# 
#              Synchronous High Speed Single Port SRAM Compiler 
# 
#                    UMC 0.18um GenericII Logic Process
#    __________________________________________________________________________
# 
# 
#      (C) Copyright 2002-2009 Faraday Technology Corp. All Rights Reserved.
#    
#    This source code is an unpublished work belongs to Faraday Technology
#    Corp.  It is considered a trade secret and is not to be divulged or
#    used by parties who have not received written authorization from
#    Faraday Technology Corp.
#    
#    Faraday's home page can be found at:
#    http://www.faraday-tech.com/
#   
#       Module Name      : SUMA180_4096X12
#       Words            : 4096
#       Bits             : 12
#       Byte-Write       : 1
#       Aspect Ratio     : 4
#       Output Loading   : 0.05  (pf)
#       Data Slew        : 0.02  (ns)
#       CK Slew          : 0.02  (ns)
#       Power Ring Width : 2  (um)
# 
# -----------------------------------------------------------------------------
# 
#       Library          : FSA0M_A
#       Memaker          : 200901.2.1
#       Date             : 2026/05/01 20:58:27
# 
# -----------------------------------------------------------------------------


NAMESCASESENSITIVE ON ;
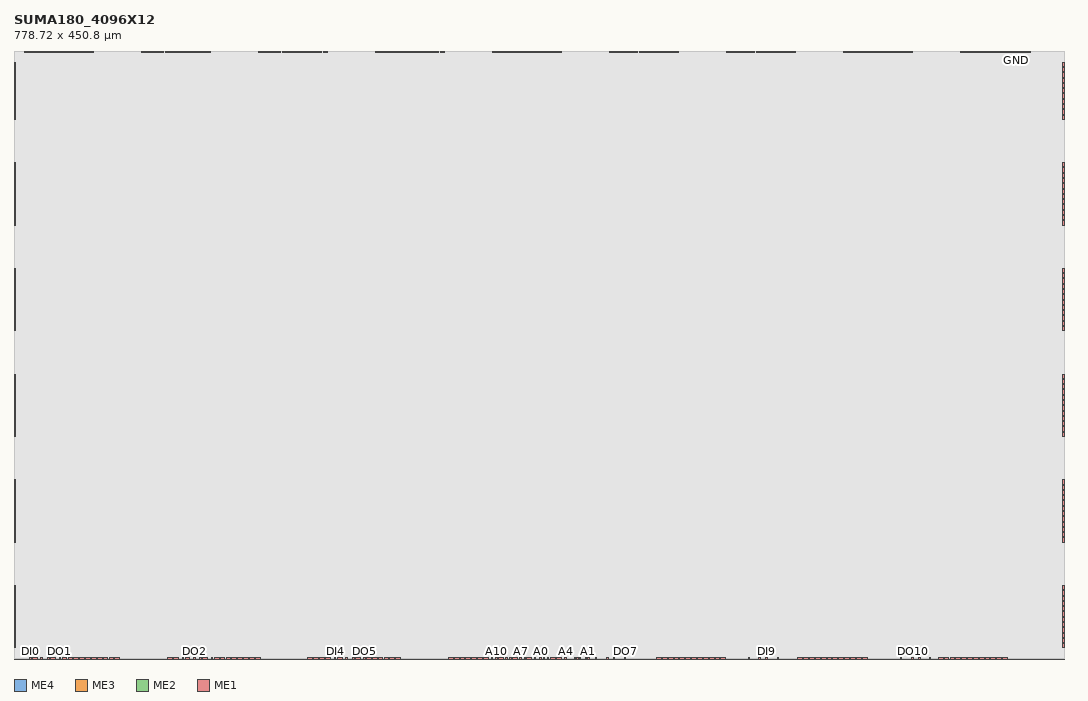
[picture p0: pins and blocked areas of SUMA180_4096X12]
MACRO SUMA180_4096X12
CLASS BLOCK ;
FOREIGN SUMA180_4096X12 0.000 0.000 ;
ORIGIN 0.000 0.000 ;
SIZE 778.720 BY 450.800 ;
SYMMETRY x y r90 ;
SITE core ;
PIN VCC
  DIRECTION INOUT ;
  USE POWER ;
  SHAPE ABUTMENT ;
 PORT
  LAYER ME4 ;
  RECT 777.600 439.380 778.720 442.620 ;
  LAYER ME3 ;
  RECT 777.600 439.380 778.720 442.620 ;
  LAYER ME2 ;
  RECT 777.600 439.380 778.720 442.620 ;
  LAYER ME1 ;
  RECT 777.600 439.380 778.720 442.620 ;
 END
 PORT
  LAYER ME4 ;
  RECT 777.600 431.540 778.720 434.780 ;
  LAYER ME3 ;
  RECT 777.600 431.540 778.720 434.780 ;
  LAYER ME2 ;
  RECT 777.600 431.540 778.720 434.780 ;
  LAYER ME1 ;
  RECT 777.600 431.540 778.720 434.780 ;
 END
 PORT
  LAYER ME4 ;
  RECT 777.600 423.700 778.720 426.940 ;
  LAYER ME3 ;
  RECT 777.600 423.700 778.720 426.940 ;
  LAYER ME2 ;
  RECT 777.600 423.700 778.720 426.940 ;
  LAYER ME1 ;
  RECT 777.600 423.700 778.720 426.940 ;
 END
 PORT
  LAYER ME4 ;
  RECT 777.600 415.860 778.720 419.100 ;
  LAYER ME3 ;
  RECT 777.600 415.860 778.720 419.100 ;
  LAYER ME2 ;
  RECT 777.600 415.860 778.720 419.100 ;
  LAYER ME1 ;
  RECT 777.600 415.860 778.720 419.100 ;
 END
 PORT
  LAYER ME4 ;
  RECT 777.600 408.020 778.720 411.260 ;
  LAYER ME3 ;
  RECT 777.600 408.020 778.720 411.260 ;
  LAYER ME2 ;
  RECT 777.600 408.020 778.720 411.260 ;
  LAYER ME1 ;
  RECT 777.600 408.020 778.720 411.260 ;
 END
 PORT
  LAYER ME4 ;
  RECT 777.600 400.180 778.720 403.420 ;
  LAYER ME3 ;
  RECT 777.600 400.180 778.720 403.420 ;
  LAYER ME2 ;
  RECT 777.600 400.180 778.720 403.420 ;
  LAYER ME1 ;
  RECT 777.600 400.180 778.720 403.420 ;
 END
 PORT
  LAYER ME4 ;
  RECT 777.600 360.980 778.720 364.220 ;
  LAYER ME3 ;
  RECT 777.600 360.980 778.720 364.220 ;
  LAYER ME2 ;
  RECT 777.600 360.980 778.720 364.220 ;
  LAYER ME1 ;
  RECT 777.600 360.980 778.720 364.220 ;
 END
 PORT
  LAYER ME4 ;
  RECT 777.600 353.140 778.720 356.380 ;
  LAYER ME3 ;
  RECT 777.600 353.140 778.720 356.380 ;
  LAYER ME2 ;
  RECT 777.600 353.140 778.720 356.380 ;
  LAYER ME1 ;
  RECT 777.600 353.140 778.720 356.380 ;
 END
 PORT
  LAYER ME4 ;
  RECT 777.600 345.300 778.720 348.540 ;
  LAYER ME3 ;
  RECT 777.600 345.300 778.720 348.540 ;
  LAYER ME2 ;
  RECT 777.600 345.300 778.720 348.540 ;
  LAYER ME1 ;
  RECT 777.600 345.300 778.720 348.540 ;
 END
 PORT
  LAYER ME4 ;
  RECT 777.600 337.460 778.720 340.700 ;
  LAYER ME3 ;
  RECT 777.600 337.460 778.720 340.700 ;
  LAYER ME2 ;
  RECT 777.600 337.460 778.720 340.700 ;
  LAYER ME1 ;
  RECT 777.600 337.460 778.720 340.700 ;
 END
 PORT
  LAYER ME4 ;
  RECT 777.600 329.620 778.720 332.860 ;
  LAYER ME3 ;
  RECT 777.600 329.620 778.720 332.860 ;
  LAYER ME2 ;
  RECT 777.600 329.620 778.720 332.860 ;
  LAYER ME1 ;
  RECT 777.600 329.620 778.720 332.860 ;
 END
 PORT
  LAYER ME4 ;
  RECT 777.600 321.780 778.720 325.020 ;
  LAYER ME3 ;
  RECT 777.600 321.780 778.720 325.020 ;
  LAYER ME2 ;
  RECT 777.600 321.780 778.720 325.020 ;
  LAYER ME1 ;
  RECT 777.600 321.780 778.720 325.020 ;
 END
 PORT
  LAYER ME4 ;
  RECT 777.600 282.580 778.720 285.820 ;
  LAYER ME3 ;
  RECT 777.600 282.580 778.720 285.820 ;
  LAYER ME2 ;
  RECT 777.600 282.580 778.720 285.820 ;
  LAYER ME1 ;
  RECT 777.600 282.580 778.720 285.820 ;
 END
 PORT
  LAYER ME4 ;
  RECT 777.600 274.740 778.720 277.980 ;
  LAYER ME3 ;
  RECT 777.600 274.740 778.720 277.980 ;
  LAYER ME2 ;
  RECT 777.600 274.740 778.720 277.980 ;
  LAYER ME1 ;
  RECT 777.600 274.740 778.720 277.980 ;
 END
 PORT
  LAYER ME4 ;
  RECT 777.600 266.900 778.720 270.140 ;
  LAYER ME3 ;
  RECT 777.600 266.900 778.720 270.140 ;
  LAYER ME2 ;
  RECT 777.600 266.900 778.720 270.140 ;
  LAYER ME1 ;
  RECT 777.600 266.900 778.720 270.140 ;
 END
 PORT
  LAYER ME4 ;
  RECT 777.600 259.060 778.720 262.300 ;
  LAYER ME3 ;
  RECT 777.600 259.060 778.720 262.300 ;
  LAYER ME2 ;
  RECT 777.600 259.060 778.720 262.300 ;
  LAYER ME1 ;
  RECT 777.600 259.060 778.720 262.300 ;
 END
 PORT
  LAYER ME4 ;
  RECT 777.600 251.220 778.720 254.460 ;
  LAYER ME3 ;
  RECT 777.600 251.220 778.720 254.460 ;
  LAYER ME2 ;
  RECT 777.600 251.220 778.720 254.460 ;
  LAYER ME1 ;
  RECT 777.600 251.220 778.720 254.460 ;
 END
 PORT
  LAYER ME4 ;
  RECT 777.600 243.380 778.720 246.620 ;
  LAYER ME3 ;
  RECT 777.600 243.380 778.720 246.620 ;
  LAYER ME2 ;
  RECT 777.600 243.380 778.720 246.620 ;
  LAYER ME1 ;
  RECT 777.600 243.380 778.720 246.620 ;
 END
 PORT
  LAYER ME4 ;
  RECT 777.600 204.180 778.720 207.420 ;
  LAYER ME3 ;
  RECT 777.600 204.180 778.720 207.420 ;
  LAYER ME2 ;
  RECT 777.600 204.180 778.720 207.420 ;
  LAYER ME1 ;
  RECT 777.600 204.180 778.720 207.420 ;
 END
 PORT
  LAYER ME4 ;
  RECT 777.600 196.340 778.720 199.580 ;
  LAYER ME3 ;
  RECT 777.600 196.340 778.720 199.580 ;
  LAYER ME2 ;
  RECT 777.600 196.340 778.720 199.580 ;
  LAYER ME1 ;
  RECT 777.600 196.340 778.720 199.580 ;
 END
 PORT
  LAYER ME4 ;
  RECT 777.600 188.500 778.720 191.740 ;
  LAYER ME3 ;
  RECT 777.600 188.500 778.720 191.740 ;
  LAYER ME2 ;
  RECT 777.600 188.500 778.720 191.740 ;
  LAYER ME1 ;
  RECT 777.600 188.500 778.720 191.740 ;
 END
 PORT
  LAYER ME4 ;
  RECT 777.600 180.660 778.720 183.900 ;
  LAYER ME3 ;
  RECT 777.600 180.660 778.720 183.900 ;
  LAYER ME2 ;
  RECT 777.600 180.660 778.720 183.900 ;
  LAYER ME1 ;
  RECT 777.600 180.660 778.720 183.900 ;
 END
 PORT
  LAYER ME4 ;
  RECT 777.600 172.820 778.720 176.060 ;
  LAYER ME3 ;
  RECT 777.600 172.820 778.720 176.060 ;
  LAYER ME2 ;
  RECT 777.600 172.820 778.720 176.060 ;
  LAYER ME1 ;
  RECT 777.600 172.820 778.720 176.060 ;
 END
 PORT
  LAYER ME4 ;
  RECT 777.600 164.980 778.720 168.220 ;
  LAYER ME3 ;
  RECT 777.600 164.980 778.720 168.220 ;
  LAYER ME2 ;
  RECT 777.600 164.980 778.720 168.220 ;
  LAYER ME1 ;
  RECT 777.600 164.980 778.720 168.220 ;
 END
 PORT
  LAYER ME4 ;
  RECT 777.600 125.780 778.720 129.020 ;
  LAYER ME3 ;
  RECT 777.600 125.780 778.720 129.020 ;
  LAYER ME2 ;
  RECT 777.600 125.780 778.720 129.020 ;
  LAYER ME1 ;
  RECT 777.600 125.780 778.720 129.020 ;
 END
 PORT
  LAYER ME4 ;
  RECT 777.600 117.940 778.720 121.180 ;
  LAYER ME3 ;
  RECT 777.600 117.940 778.720 121.180 ;
  LAYER ME2 ;
  RECT 777.600 117.940 778.720 121.180 ;
  LAYER ME1 ;
  RECT 777.600 117.940 778.720 121.180 ;
 END
 PORT
  LAYER ME4 ;
  RECT 777.600 110.100 778.720 113.340 ;
  LAYER ME3 ;
  RECT 777.600 110.100 778.720 113.340 ;
  LAYER ME2 ;
  RECT 777.600 110.100 778.720 113.340 ;
  LAYER ME1 ;
  RECT 777.600 110.100 778.720 113.340 ;
 END
 PORT
  LAYER ME4 ;
  RECT 777.600 102.260 778.720 105.500 ;
  LAYER ME3 ;
  RECT 777.600 102.260 778.720 105.500 ;
  LAYER ME2 ;
  RECT 777.600 102.260 778.720 105.500 ;
  LAYER ME1 ;
  RECT 777.600 102.260 778.720 105.500 ;
 END
 PORT
  LAYER ME4 ;
  RECT 777.600 94.420 778.720 97.660 ;
  LAYER ME3 ;
  RECT 777.600 94.420 778.720 97.660 ;
  LAYER ME2 ;
  RECT 777.600 94.420 778.720 97.660 ;
  LAYER ME1 ;
  RECT 777.600 94.420 778.720 97.660 ;
 END
 PORT
  LAYER ME4 ;
  RECT 777.600 86.580 778.720 89.820 ;
  LAYER ME3 ;
  RECT 777.600 86.580 778.720 89.820 ;
  LAYER ME2 ;
  RECT 777.600 86.580 778.720 89.820 ;
  LAYER ME1 ;
  RECT 777.600 86.580 778.720 89.820 ;
 END
 PORT
  LAYER ME4 ;
  RECT 777.600 47.380 778.720 50.620 ;
  LAYER ME3 ;
  RECT 777.600 47.380 778.720 50.620 ;
  LAYER ME2 ;
  RECT 777.600 47.380 778.720 50.620 ;
  LAYER ME1 ;
  RECT 777.600 47.380 778.720 50.620 ;
 END
 PORT
  LAYER ME4 ;
  RECT 777.600 39.540 778.720 42.780 ;
  LAYER ME3 ;
  RECT 777.600 39.540 778.720 42.780 ;
  LAYER ME2 ;
  RECT 777.600 39.540 778.720 42.780 ;
  LAYER ME1 ;
  RECT 777.600 39.540 778.720 42.780 ;
 END
 PORT
  LAYER ME4 ;
  RECT 777.600 31.700 778.720 34.940 ;
  LAYER ME3 ;
  RECT 777.600 31.700 778.720 34.940 ;
  LAYER ME2 ;
  RECT 777.600 31.700 778.720 34.940 ;
  LAYER ME1 ;
  RECT 777.600 31.700 778.720 34.940 ;
 END
 PORT
  LAYER ME4 ;
  RECT 777.600 23.860 778.720 27.100 ;
  LAYER ME3 ;
  RECT 777.600 23.860 778.720 27.100 ;
  LAYER ME2 ;
  RECT 777.600 23.860 778.720 27.100 ;
  LAYER ME1 ;
  RECT 777.600 23.860 778.720 27.100 ;
 END
 PORT
  LAYER ME4 ;
  RECT 777.600 16.020 778.720 19.260 ;
  LAYER ME3 ;
  RECT 777.600 16.020 778.720 19.260 ;
  LAYER ME2 ;
  RECT 777.600 16.020 778.720 19.260 ;
  LAYER ME1 ;
  RECT 777.600 16.020 778.720 19.260 ;
 END
 PORT
  LAYER ME4 ;
  RECT 777.600 8.180 778.720 11.420 ;
  LAYER ME3 ;
  RECT 777.600 8.180 778.720 11.420 ;
  LAYER ME2 ;
  RECT 777.600 8.180 778.720 11.420 ;
  LAYER ME1 ;
  RECT 777.600 8.180 778.720 11.420 ;
 END
 PORT
  LAYER ME4 ;
  RECT 0.000 439.380 1.120 442.620 ;
  LAYER ME3 ;
  RECT 0.000 439.380 1.120 442.620 ;
  LAYER ME2 ;
  RECT 0.000 439.380 1.120 442.620 ;
  LAYER ME1 ;
  RECT 0.000 439.380 1.120 442.620 ;
 END
 PORT
  LAYER ME4 ;
  RECT 0.000 431.540 1.120 434.780 ;
  LAYER ME3 ;
  RECT 0.000 431.540 1.120 434.780 ;
  LAYER ME2 ;
  RECT 0.000 431.540 1.120 434.780 ;
  LAYER ME1 ;
  RECT 0.000 431.540 1.120 434.780 ;
 END
 PORT
  LAYER ME4 ;
  RECT 0.000 423.700 1.120 426.940 ;
  LAYER ME3 ;
  RECT 0.000 423.700 1.120 426.940 ;
  LAYER ME2 ;
  RECT 0.000 423.700 1.120 426.940 ;
  LAYER ME1 ;
  RECT 0.000 423.700 1.120 426.940 ;
 END
 PORT
  LAYER ME4 ;
  RECT 0.000 415.860 1.120 419.100 ;
  LAYER ME3 ;
  RECT 0.000 415.860 1.120 419.100 ;
  LAYER ME2 ;
  RECT 0.000 415.860 1.120 419.100 ;
  LAYER ME1 ;
  RECT 0.000 415.860 1.120 419.100 ;
 END
 PORT
  LAYER ME4 ;
  RECT 0.000 408.020 1.120 411.260 ;
  LAYER ME3 ;
  RECT 0.000 408.020 1.120 411.260 ;
  LAYER ME2 ;
  RECT 0.000 408.020 1.120 411.260 ;
  LAYER ME1 ;
  RECT 0.000 408.020 1.120 411.260 ;
 END
 PORT
  LAYER ME4 ;
  RECT 0.000 400.180 1.120 403.420 ;
  LAYER ME3 ;
  RECT 0.000 400.180 1.120 403.420 ;
  LAYER ME2 ;
  RECT 0.000 400.180 1.120 403.420 ;
  LAYER ME1 ;
  RECT 0.000 400.180 1.120 403.420 ;
 END
 PORT
  LAYER ME4 ;
  RECT 0.000 360.980 1.120 364.220 ;
  LAYER ME3 ;
  RECT 0.000 360.980 1.120 364.220 ;
  LAYER ME2 ;
  RECT 0.000 360.980 1.120 364.220 ;
  LAYER ME1 ;
  RECT 0.000 360.980 1.120 364.220 ;
 END
 PORT
  LAYER ME4 ;
  RECT 0.000 353.140 1.120 356.380 ;
  LAYER ME3 ;
  RECT 0.000 353.140 1.120 356.380 ;
  LAYER ME2 ;
  RECT 0.000 353.140 1.120 356.380 ;
  LAYER ME1 ;
  RECT 0.000 353.140 1.120 356.380 ;
 END
 PORT
  LAYER ME4 ;
  RECT 0.000 345.300 1.120 348.540 ;
  LAYER ME3 ;
  RECT 0.000 345.300 1.120 348.540 ;
  LAYER ME2 ;
  RECT 0.000 345.300 1.120 348.540 ;
  LAYER ME1 ;
  RECT 0.000 345.300 1.120 348.540 ;
 END
 PORT
  LAYER ME4 ;
  RECT 0.000 337.460 1.120 340.700 ;
  LAYER ME3 ;
  RECT 0.000 337.460 1.120 340.700 ;
  LAYER ME2 ;
  RECT 0.000 337.460 1.120 340.700 ;
  LAYER ME1 ;
  RECT 0.000 337.460 1.120 340.700 ;
 END
 PORT
  LAYER ME4 ;
  RECT 0.000 329.620 1.120 332.860 ;
  LAYER ME3 ;
  RECT 0.000 329.620 1.120 332.860 ;
  LAYER ME2 ;
  RECT 0.000 329.620 1.120 332.860 ;
  LAYER ME1 ;
  RECT 0.000 329.620 1.120 332.860 ;
 END
 PORT
  LAYER ME4 ;
  RECT 0.000 321.780 1.120 325.020 ;
  LAYER ME3 ;
  RECT 0.000 321.780 1.120 325.020 ;
  LAYER ME2 ;
  RECT 0.000 321.780 1.120 325.020 ;
  LAYER ME1 ;
  RECT 0.000 321.780 1.120 325.020 ;
 END
 PORT
  LAYER ME4 ;
  RECT 0.000 282.580 1.120 285.820 ;
  LAYER ME3 ;
  RECT 0.000 282.580 1.120 285.820 ;
  LAYER ME2 ;
  RECT 0.000 282.580 1.120 285.820 ;
  LAYER ME1 ;
  RECT 0.000 282.580 1.120 285.820 ;
 END
 PORT
  LAYER ME4 ;
  RECT 0.000 274.740 1.120 277.980 ;
  LAYER ME3 ;
  RECT 0.000 274.740 1.120 277.980 ;
  LAYER ME2 ;
  RECT 0.000 274.740 1.120 277.980 ;
  LAYER ME1 ;
  RECT 0.000 274.740 1.120 277.980 ;
 END
 PORT
  LAYER ME4 ;
  RECT 0.000 266.900 1.120 270.140 ;
  LAYER ME3 ;
  RECT 0.000 266.900 1.120 270.140 ;
  LAYER ME2 ;
  RECT 0.000 266.900 1.120 270.140 ;
  LAYER ME1 ;
  RECT 0.000 266.900 1.120 270.140 ;
 END
 PORT
  LAYER ME4 ;
  RECT 0.000 259.060 1.120 262.300 ;
  LAYER ME3 ;
  RECT 0.000 259.060 1.120 262.300 ;
  LAYER ME2 ;
  RECT 0.000 259.060 1.120 262.300 ;
  LAYER ME1 ;
  RECT 0.000 259.060 1.120 262.300 ;
 END
 PORT
  LAYER ME4 ;
  RECT 0.000 251.220 1.120 254.460 ;
  LAYER ME3 ;
  RECT 0.000 251.220 1.120 254.460 ;
  LAYER ME2 ;
  RECT 0.000 251.220 1.120 254.460 ;
  LAYER ME1 ;
  RECT 0.000 251.220 1.120 254.460 ;
 END
 PORT
  LAYER ME4 ;
  RECT 0.000 243.380 1.120 246.620 ;
  LAYER ME3 ;
  RECT 0.000 243.380 1.120 246.620 ;
  LAYER ME2 ;
  RECT 0.000 243.380 1.120 246.620 ;
  LAYER ME1 ;
  RECT 0.000 243.380 1.120 246.620 ;
 END
 PORT
  LAYER ME4 ;
  RECT 0.000 204.180 1.120 207.420 ;
  LAYER ME3 ;
  RECT 0.000 204.180 1.120 207.420 ;
  LAYER ME2 ;
  RECT 0.000 204.180 1.120 207.420 ;
  LAYER ME1 ;
  RECT 0.000 204.180 1.120 207.420 ;
 END
 PORT
  LAYER ME4 ;
  RECT 0.000 196.340 1.120 199.580 ;
  LAYER ME3 ;
  RECT 0.000 196.340 1.120 199.580 ;
  LAYER ME2 ;
  RECT 0.000 196.340 1.120 199.580 ;
  LAYER ME1 ;
  RECT 0.000 196.340 1.120 199.580 ;
 END
 PORT
  LAYER ME4 ;
  RECT 0.000 188.500 1.120 191.740 ;
  LAYER ME3 ;
  RECT 0.000 188.500 1.120 191.740 ;
  LAYER ME2 ;
  RECT 0.000 188.500 1.120 191.740 ;
  LAYER ME1 ;
  RECT 0.000 188.500 1.120 191.740 ;
 END
 PORT
  LAYER ME4 ;
  RECT 0.000 180.660 1.120 183.900 ;
  LAYER ME3 ;
  RECT 0.000 180.660 1.120 183.900 ;
  LAYER ME2 ;
  RECT 0.000 180.660 1.120 183.900 ;
  LAYER ME1 ;
  RECT 0.000 180.660 1.120 183.900 ;
 END
 PORT
  LAYER ME4 ;
  RECT 0.000 172.820 1.120 176.060 ;
  LAYER ME3 ;
  RECT 0.000 172.820 1.120 176.060 ;
  LAYER ME2 ;
  RECT 0.000 172.820 1.120 176.060 ;
  LAYER ME1 ;
  RECT 0.000 172.820 1.120 176.060 ;
 END
 PORT
  LAYER ME4 ;
  RECT 0.000 164.980 1.120 168.220 ;
  LAYER ME3 ;
  RECT 0.000 164.980 1.120 168.220 ;
  LAYER ME2 ;
  RECT 0.000 164.980 1.120 168.220 ;
  LAYER ME1 ;
  RECT 0.000 164.980 1.120 168.220 ;
 END
 PORT
  LAYER ME4 ;
  RECT 0.000 125.780 1.120 129.020 ;
  LAYER ME3 ;
  RECT 0.000 125.780 1.120 129.020 ;
  LAYER ME2 ;
  RECT 0.000 125.780 1.120 129.020 ;
  LAYER ME1 ;
  RECT 0.000 125.780 1.120 129.020 ;
 END
 PORT
  LAYER ME4 ;
  RECT 0.000 117.940 1.120 121.180 ;
  LAYER ME3 ;
  RECT 0.000 117.940 1.120 121.180 ;
  LAYER ME2 ;
  RECT 0.000 117.940 1.120 121.180 ;
  LAYER ME1 ;
  RECT 0.000 117.940 1.120 121.180 ;
 END
 PORT
  LAYER ME4 ;
  RECT 0.000 110.100 1.120 113.340 ;
  LAYER ME3 ;
  RECT 0.000 110.100 1.120 113.340 ;
  LAYER ME2 ;
  RECT 0.000 110.100 1.120 113.340 ;
  LAYER ME1 ;
  RECT 0.000 110.100 1.120 113.340 ;
 END
 PORT
  LAYER ME4 ;
  RECT 0.000 102.260 1.120 105.500 ;
  LAYER ME3 ;
  RECT 0.000 102.260 1.120 105.500 ;
  LAYER ME2 ;
  RECT 0.000 102.260 1.120 105.500 ;
  LAYER ME1 ;
  RECT 0.000 102.260 1.120 105.500 ;
 END
 PORT
  LAYER ME4 ;
  RECT 0.000 94.420 1.120 97.660 ;
  LAYER ME3 ;
  RECT 0.000 94.420 1.120 97.660 ;
  LAYER ME2 ;
  RECT 0.000 94.420 1.120 97.660 ;
  LAYER ME1 ;
  RECT 0.000 94.420 1.120 97.660 ;
 END
 PORT
  LAYER ME4 ;
  RECT 0.000 86.580 1.120 89.820 ;
  LAYER ME3 ;
  RECT 0.000 86.580 1.120 89.820 ;
  LAYER ME2 ;
  RECT 0.000 86.580 1.120 89.820 ;
  LAYER ME1 ;
  RECT 0.000 86.580 1.120 89.820 ;
 END
 PORT
  LAYER ME4 ;
  RECT 0.000 47.380 1.120 50.620 ;
  LAYER ME3 ;
  RECT 0.000 47.380 1.120 50.620 ;
  LAYER ME2 ;
  RECT 0.000 47.380 1.120 50.620 ;
  LAYER ME1 ;
  RECT 0.000 47.380 1.120 50.620 ;
 END
 PORT
  LAYER ME4 ;
  RECT 0.000 39.540 1.120 42.780 ;
  LAYER ME3 ;
  RECT 0.000 39.540 1.120 42.780 ;
  LAYER ME2 ;
  RECT 0.000 39.540 1.120 42.780 ;
  LAYER ME1 ;
  RECT 0.000 39.540 1.120 42.780 ;
 END
 PORT
  LAYER ME4 ;
  RECT 0.000 31.700 1.120 34.940 ;
  LAYER ME3 ;
  RECT 0.000 31.700 1.120 34.940 ;
  LAYER ME2 ;
  RECT 0.000 31.700 1.120 34.940 ;
  LAYER ME1 ;
  RECT 0.000 31.700 1.120 34.940 ;
 END
 PORT
  LAYER ME4 ;
  RECT 0.000 23.860 1.120 27.100 ;
  LAYER ME3 ;
  RECT 0.000 23.860 1.120 27.100 ;
  LAYER ME2 ;
  RECT 0.000 23.860 1.120 27.100 ;
  LAYER ME1 ;
  RECT 0.000 23.860 1.120 27.100 ;
 END
 PORT
  LAYER ME4 ;
  RECT 0.000 16.020 1.120 19.260 ;
  LAYER ME3 ;
  RECT 0.000 16.020 1.120 19.260 ;
  LAYER ME2 ;
  RECT 0.000 16.020 1.120 19.260 ;
  LAYER ME1 ;
  RECT 0.000 16.020 1.120 19.260 ;
 END
 PORT
  LAYER ME4 ;
  RECT 0.000 8.180 1.120 11.420 ;
  LAYER ME3 ;
  RECT 0.000 8.180 1.120 11.420 ;
  LAYER ME2 ;
  RECT 0.000 8.180 1.120 11.420 ;
  LAYER ME1 ;
  RECT 0.000 8.180 1.120 11.420 ;
 END
 PORT
  LAYER ME4 ;
  RECT 745.640 449.680 749.180 450.800 ;
  LAYER ME3 ;
  RECT 745.640 449.680 749.180 450.800 ;
  LAYER ME2 ;
  RECT 745.640 449.680 749.180 450.800 ;
  LAYER ME1 ;
  RECT 745.640 449.680 749.180 450.800 ;
 END
 PORT
  LAYER ME4 ;
  RECT 736.960 449.680 740.500 450.800 ;
  LAYER ME3 ;
  RECT 736.960 449.680 740.500 450.800 ;
  LAYER ME2 ;
  RECT 736.960 449.680 740.500 450.800 ;
  LAYER ME1 ;
  RECT 736.960 449.680 740.500 450.800 ;
 END
 PORT
  LAYER ME4 ;
  RECT 728.280 449.680 731.820 450.800 ;
  LAYER ME3 ;
  RECT 728.280 449.680 731.820 450.800 ;
  LAYER ME2 ;
  RECT 728.280 449.680 731.820 450.800 ;
  LAYER ME1 ;
  RECT 728.280 449.680 731.820 450.800 ;
 END
 PORT
  LAYER ME4 ;
  RECT 719.600 449.680 723.140 450.800 ;
  LAYER ME3 ;
  RECT 719.600 449.680 723.140 450.800 ;
  LAYER ME2 ;
  RECT 719.600 449.680 723.140 450.800 ;
  LAYER ME1 ;
  RECT 719.600 449.680 723.140 450.800 ;
 END
 PORT
  LAYER ME4 ;
  RECT 710.920 449.680 714.460 450.800 ;
  LAYER ME3 ;
  RECT 710.920 449.680 714.460 450.800 ;
  LAYER ME2 ;
  RECT 710.920 449.680 714.460 450.800 ;
  LAYER ME1 ;
  RECT 710.920 449.680 714.460 450.800 ;
 END
 PORT
  LAYER ME4 ;
  RECT 702.240 449.680 705.780 450.800 ;
  LAYER ME3 ;
  RECT 702.240 449.680 705.780 450.800 ;
  LAYER ME2 ;
  RECT 702.240 449.680 705.780 450.800 ;
  LAYER ME1 ;
  RECT 702.240 449.680 705.780 450.800 ;
 END
 PORT
  LAYER ME4 ;
  RECT 658.840 449.680 662.380 450.800 ;
  LAYER ME3 ;
  RECT 658.840 449.680 662.380 450.800 ;
  LAYER ME2 ;
  RECT 658.840 449.680 662.380 450.800 ;
  LAYER ME1 ;
  RECT 658.840 449.680 662.380 450.800 ;
 END
 PORT
  LAYER ME4 ;
  RECT 650.160 449.680 653.700 450.800 ;
  LAYER ME3 ;
  RECT 650.160 449.680 653.700 450.800 ;
  LAYER ME2 ;
  RECT 650.160 449.680 653.700 450.800 ;
  LAYER ME1 ;
  RECT 650.160 449.680 653.700 450.800 ;
 END
 PORT
  LAYER ME4 ;
  RECT 641.480 449.680 645.020 450.800 ;
  LAYER ME3 ;
  RECT 641.480 449.680 645.020 450.800 ;
  LAYER ME2 ;
  RECT 641.480 449.680 645.020 450.800 ;
  LAYER ME1 ;
  RECT 641.480 449.680 645.020 450.800 ;
 END
 PORT
  LAYER ME4 ;
  RECT 632.800 449.680 636.340 450.800 ;
  LAYER ME3 ;
  RECT 632.800 449.680 636.340 450.800 ;
  LAYER ME2 ;
  RECT 632.800 449.680 636.340 450.800 ;
  LAYER ME1 ;
  RECT 632.800 449.680 636.340 450.800 ;
 END
 PORT
  LAYER ME4 ;
  RECT 624.120 449.680 627.660 450.800 ;
  LAYER ME3 ;
  RECT 624.120 449.680 627.660 450.800 ;
  LAYER ME2 ;
  RECT 624.120 449.680 627.660 450.800 ;
  LAYER ME1 ;
  RECT 624.120 449.680 627.660 450.800 ;
 END
 PORT
  LAYER ME4 ;
  RECT 615.440 449.680 618.980 450.800 ;
  LAYER ME3 ;
  RECT 615.440 449.680 618.980 450.800 ;
  LAYER ME2 ;
  RECT 615.440 449.680 618.980 450.800 ;
  LAYER ME1 ;
  RECT 615.440 449.680 618.980 450.800 ;
 END
 PORT
  LAYER ME4 ;
  RECT 572.040 449.680 575.580 450.800 ;
  LAYER ME3 ;
  RECT 572.040 449.680 575.580 450.800 ;
  LAYER ME2 ;
  RECT 572.040 449.680 575.580 450.800 ;
  LAYER ME1 ;
  RECT 572.040 449.680 575.580 450.800 ;
 END
 PORT
  LAYER ME4 ;
  RECT 563.360 449.680 566.900 450.800 ;
  LAYER ME3 ;
  RECT 563.360 449.680 566.900 450.800 ;
  LAYER ME2 ;
  RECT 563.360 449.680 566.900 450.800 ;
  LAYER ME1 ;
  RECT 563.360 449.680 566.900 450.800 ;
 END
 PORT
  LAYER ME4 ;
  RECT 554.680 449.680 558.220 450.800 ;
  LAYER ME3 ;
  RECT 554.680 449.680 558.220 450.800 ;
  LAYER ME2 ;
  RECT 554.680 449.680 558.220 450.800 ;
  LAYER ME1 ;
  RECT 554.680 449.680 558.220 450.800 ;
 END
 PORT
  LAYER ME4 ;
  RECT 546.000 449.680 549.540 450.800 ;
  LAYER ME3 ;
  RECT 546.000 449.680 549.540 450.800 ;
  LAYER ME2 ;
  RECT 546.000 449.680 549.540 450.800 ;
  LAYER ME1 ;
  RECT 546.000 449.680 549.540 450.800 ;
 END
 PORT
  LAYER ME4 ;
  RECT 537.320 449.680 540.860 450.800 ;
  LAYER ME3 ;
  RECT 537.320 449.680 540.860 450.800 ;
  LAYER ME2 ;
  RECT 537.320 449.680 540.860 450.800 ;
  LAYER ME1 ;
  RECT 537.320 449.680 540.860 450.800 ;
 END
 PORT
  LAYER ME4 ;
  RECT 528.640 449.680 532.180 450.800 ;
  LAYER ME3 ;
  RECT 528.640 449.680 532.180 450.800 ;
  LAYER ME2 ;
  RECT 528.640 449.680 532.180 450.800 ;
  LAYER ME1 ;
  RECT 528.640 449.680 532.180 450.800 ;
 END
 PORT
  LAYER ME4 ;
  RECT 485.240 449.680 488.780 450.800 ;
  LAYER ME3 ;
  RECT 485.240 449.680 488.780 450.800 ;
  LAYER ME2 ;
  RECT 485.240 449.680 488.780 450.800 ;
  LAYER ME1 ;
  RECT 485.240 449.680 488.780 450.800 ;
 END
 PORT
  LAYER ME4 ;
  RECT 476.560 449.680 480.100 450.800 ;
  LAYER ME3 ;
  RECT 476.560 449.680 480.100 450.800 ;
  LAYER ME2 ;
  RECT 476.560 449.680 480.100 450.800 ;
  LAYER ME1 ;
  RECT 476.560 449.680 480.100 450.800 ;
 END
 PORT
  LAYER ME4 ;
  RECT 467.880 449.680 471.420 450.800 ;
  LAYER ME3 ;
  RECT 467.880 449.680 471.420 450.800 ;
  LAYER ME2 ;
  RECT 467.880 449.680 471.420 450.800 ;
  LAYER ME1 ;
  RECT 467.880 449.680 471.420 450.800 ;
 END
 PORT
  LAYER ME4 ;
  RECT 459.200 449.680 462.740 450.800 ;
  LAYER ME3 ;
  RECT 459.200 449.680 462.740 450.800 ;
  LAYER ME2 ;
  RECT 459.200 449.680 462.740 450.800 ;
  LAYER ME1 ;
  RECT 459.200 449.680 462.740 450.800 ;
 END
 PORT
  LAYER ME4 ;
  RECT 450.520 449.680 454.060 450.800 ;
  LAYER ME3 ;
  RECT 450.520 449.680 454.060 450.800 ;
  LAYER ME2 ;
  RECT 450.520 449.680 454.060 450.800 ;
  LAYER ME1 ;
  RECT 450.520 449.680 454.060 450.800 ;
 END
 PORT
  LAYER ME4 ;
  RECT 441.840 449.680 445.380 450.800 ;
  LAYER ME3 ;
  RECT 441.840 449.680 445.380 450.800 ;
  LAYER ME2 ;
  RECT 441.840 449.680 445.380 450.800 ;
  LAYER ME1 ;
  RECT 441.840 449.680 445.380 450.800 ;
 END
 PORT
  LAYER ME4 ;
  RECT 398.440 449.680 401.980 450.800 ;
  LAYER ME3 ;
  RECT 398.440 449.680 401.980 450.800 ;
  LAYER ME2 ;
  RECT 398.440 449.680 401.980 450.800 ;
  LAYER ME1 ;
  RECT 398.440 449.680 401.980 450.800 ;
 END
 PORT
  LAYER ME4 ;
  RECT 389.760 449.680 393.300 450.800 ;
  LAYER ME3 ;
  RECT 389.760 449.680 393.300 450.800 ;
  LAYER ME2 ;
  RECT 389.760 449.680 393.300 450.800 ;
  LAYER ME1 ;
  RECT 389.760 449.680 393.300 450.800 ;
 END
 PORT
  LAYER ME4 ;
  RECT 381.080 449.680 384.620 450.800 ;
  LAYER ME3 ;
  RECT 381.080 449.680 384.620 450.800 ;
  LAYER ME2 ;
  RECT 381.080 449.680 384.620 450.800 ;
  LAYER ME1 ;
  RECT 381.080 449.680 384.620 450.800 ;
 END
 PORT
  LAYER ME4 ;
  RECT 372.400 449.680 375.940 450.800 ;
  LAYER ME3 ;
  RECT 372.400 449.680 375.940 450.800 ;
  LAYER ME2 ;
  RECT 372.400 449.680 375.940 450.800 ;
  LAYER ME1 ;
  RECT 372.400 449.680 375.940 450.800 ;
 END
 PORT
  LAYER ME4 ;
  RECT 363.720 449.680 367.260 450.800 ;
  LAYER ME3 ;
  RECT 363.720 449.680 367.260 450.800 ;
  LAYER ME2 ;
  RECT 363.720 449.680 367.260 450.800 ;
  LAYER ME1 ;
  RECT 363.720 449.680 367.260 450.800 ;
 END
 PORT
  LAYER ME4 ;
  RECT 355.040 449.680 358.580 450.800 ;
  LAYER ME3 ;
  RECT 355.040 449.680 358.580 450.800 ;
  LAYER ME2 ;
  RECT 355.040 449.680 358.580 450.800 ;
  LAYER ME1 ;
  RECT 355.040 449.680 358.580 450.800 ;
 END
 PORT
  LAYER ME4 ;
  RECT 311.640 449.680 315.180 450.800 ;
  LAYER ME3 ;
  RECT 311.640 449.680 315.180 450.800 ;
  LAYER ME2 ;
  RECT 311.640 449.680 315.180 450.800 ;
  LAYER ME1 ;
  RECT 311.640 449.680 315.180 450.800 ;
 END
 PORT
  LAYER ME4 ;
  RECT 302.960 449.680 306.500 450.800 ;
  LAYER ME3 ;
  RECT 302.960 449.680 306.500 450.800 ;
  LAYER ME2 ;
  RECT 302.960 449.680 306.500 450.800 ;
  LAYER ME1 ;
  RECT 302.960 449.680 306.500 450.800 ;
 END
 PORT
  LAYER ME4 ;
  RECT 294.280 449.680 297.820 450.800 ;
  LAYER ME3 ;
  RECT 294.280 449.680 297.820 450.800 ;
  LAYER ME2 ;
  RECT 294.280 449.680 297.820 450.800 ;
  LAYER ME1 ;
  RECT 294.280 449.680 297.820 450.800 ;
 END
 PORT
  LAYER ME4 ;
  RECT 285.600 449.680 289.140 450.800 ;
  LAYER ME3 ;
  RECT 285.600 449.680 289.140 450.800 ;
  LAYER ME2 ;
  RECT 285.600 449.680 289.140 450.800 ;
  LAYER ME1 ;
  RECT 285.600 449.680 289.140 450.800 ;
 END
 PORT
  LAYER ME4 ;
  RECT 276.920 449.680 280.460 450.800 ;
  LAYER ME3 ;
  RECT 276.920 449.680 280.460 450.800 ;
  LAYER ME2 ;
  RECT 276.920 449.680 280.460 450.800 ;
  LAYER ME1 ;
  RECT 276.920 449.680 280.460 450.800 ;
 END
 PORT
  LAYER ME4 ;
  RECT 268.240 449.680 271.780 450.800 ;
  LAYER ME3 ;
  RECT 268.240 449.680 271.780 450.800 ;
  LAYER ME2 ;
  RECT 268.240 449.680 271.780 450.800 ;
  LAYER ME1 ;
  RECT 268.240 449.680 271.780 450.800 ;
 END
 PORT
  LAYER ME4 ;
  RECT 224.840 449.680 228.380 450.800 ;
  LAYER ME3 ;
  RECT 224.840 449.680 228.380 450.800 ;
  LAYER ME2 ;
  RECT 224.840 449.680 228.380 450.800 ;
  LAYER ME1 ;
  RECT 224.840 449.680 228.380 450.800 ;
 END
 PORT
  LAYER ME4 ;
  RECT 216.160 449.680 219.700 450.800 ;
  LAYER ME3 ;
  RECT 216.160 449.680 219.700 450.800 ;
  LAYER ME2 ;
  RECT 216.160 449.680 219.700 450.800 ;
  LAYER ME1 ;
  RECT 216.160 449.680 219.700 450.800 ;
 END
 PORT
  LAYER ME4 ;
  RECT 207.480 449.680 211.020 450.800 ;
  LAYER ME3 ;
  RECT 207.480 449.680 211.020 450.800 ;
  LAYER ME2 ;
  RECT 207.480 449.680 211.020 450.800 ;
  LAYER ME1 ;
  RECT 207.480 449.680 211.020 450.800 ;
 END
 PORT
  LAYER ME4 ;
  RECT 198.800 449.680 202.340 450.800 ;
  LAYER ME3 ;
  RECT 198.800 449.680 202.340 450.800 ;
  LAYER ME2 ;
  RECT 198.800 449.680 202.340 450.800 ;
  LAYER ME1 ;
  RECT 198.800 449.680 202.340 450.800 ;
 END
 PORT
  LAYER ME4 ;
  RECT 190.120 449.680 193.660 450.800 ;
  LAYER ME3 ;
  RECT 190.120 449.680 193.660 450.800 ;
  LAYER ME2 ;
  RECT 190.120 449.680 193.660 450.800 ;
  LAYER ME1 ;
  RECT 190.120 449.680 193.660 450.800 ;
 END
 PORT
  LAYER ME4 ;
  RECT 181.440 449.680 184.980 450.800 ;
  LAYER ME3 ;
  RECT 181.440 449.680 184.980 450.800 ;
  LAYER ME2 ;
  RECT 181.440 449.680 184.980 450.800 ;
  LAYER ME1 ;
  RECT 181.440 449.680 184.980 450.800 ;
 END
 PORT
  LAYER ME4 ;
  RECT 138.040 449.680 141.580 450.800 ;
  LAYER ME3 ;
  RECT 138.040 449.680 141.580 450.800 ;
  LAYER ME2 ;
  RECT 138.040 449.680 141.580 450.800 ;
  LAYER ME1 ;
  RECT 138.040 449.680 141.580 450.800 ;
 END
 PORT
  LAYER ME4 ;
  RECT 129.360 449.680 132.900 450.800 ;
  LAYER ME3 ;
  RECT 129.360 449.680 132.900 450.800 ;
  LAYER ME2 ;
  RECT 129.360 449.680 132.900 450.800 ;
  LAYER ME1 ;
  RECT 129.360 449.680 132.900 450.800 ;
 END
 PORT
  LAYER ME4 ;
  RECT 120.680 449.680 124.220 450.800 ;
  LAYER ME3 ;
  RECT 120.680 449.680 124.220 450.800 ;
  LAYER ME2 ;
  RECT 120.680 449.680 124.220 450.800 ;
  LAYER ME1 ;
  RECT 120.680 449.680 124.220 450.800 ;
 END
 PORT
  LAYER ME4 ;
  RECT 112.000 449.680 115.540 450.800 ;
  LAYER ME3 ;
  RECT 112.000 449.680 115.540 450.800 ;
  LAYER ME2 ;
  RECT 112.000 449.680 115.540 450.800 ;
  LAYER ME1 ;
  RECT 112.000 449.680 115.540 450.800 ;
 END
 PORT
  LAYER ME4 ;
  RECT 103.320 449.680 106.860 450.800 ;
  LAYER ME3 ;
  RECT 103.320 449.680 106.860 450.800 ;
  LAYER ME2 ;
  RECT 103.320 449.680 106.860 450.800 ;
  LAYER ME1 ;
  RECT 103.320 449.680 106.860 450.800 ;
 END
 PORT
  LAYER ME4 ;
  RECT 94.640 449.680 98.180 450.800 ;
  LAYER ME3 ;
  RECT 94.640 449.680 98.180 450.800 ;
  LAYER ME2 ;
  RECT 94.640 449.680 98.180 450.800 ;
  LAYER ME1 ;
  RECT 94.640 449.680 98.180 450.800 ;
 END
 PORT
  LAYER ME4 ;
  RECT 51.240 449.680 54.780 450.800 ;
  LAYER ME3 ;
  RECT 51.240 449.680 54.780 450.800 ;
  LAYER ME2 ;
  RECT 51.240 449.680 54.780 450.800 ;
  LAYER ME1 ;
  RECT 51.240 449.680 54.780 450.800 ;
 END
 PORT
  LAYER ME4 ;
  RECT 42.560 449.680 46.100 450.800 ;
  LAYER ME3 ;
  RECT 42.560 449.680 46.100 450.800 ;
  LAYER ME2 ;
  RECT 42.560 449.680 46.100 450.800 ;
  LAYER ME1 ;
  RECT 42.560 449.680 46.100 450.800 ;
 END
 PORT
  LAYER ME4 ;
  RECT 33.880 449.680 37.420 450.800 ;
  LAYER ME3 ;
  RECT 33.880 449.680 37.420 450.800 ;
  LAYER ME2 ;
  RECT 33.880 449.680 37.420 450.800 ;
  LAYER ME1 ;
  RECT 33.880 449.680 37.420 450.800 ;
 END
 PORT
  LAYER ME4 ;
  RECT 25.200 449.680 28.740 450.800 ;
  LAYER ME3 ;
  RECT 25.200 449.680 28.740 450.800 ;
  LAYER ME2 ;
  RECT 25.200 449.680 28.740 450.800 ;
  LAYER ME1 ;
  RECT 25.200 449.680 28.740 450.800 ;
 END
 PORT
  LAYER ME4 ;
  RECT 16.520 449.680 20.060 450.800 ;
  LAYER ME3 ;
  RECT 16.520 449.680 20.060 450.800 ;
  LAYER ME2 ;
  RECT 16.520 449.680 20.060 450.800 ;
  LAYER ME1 ;
  RECT 16.520 449.680 20.060 450.800 ;
 END
 PORT
  LAYER ME4 ;
  RECT 7.840 449.680 11.380 450.800 ;
  LAYER ME3 ;
  RECT 7.840 449.680 11.380 450.800 ;
  LAYER ME2 ;
  RECT 7.840 449.680 11.380 450.800 ;
  LAYER ME1 ;
  RECT 7.840 449.680 11.380 450.800 ;
 END
 PORT
  LAYER ME4 ;
  RECT 728.900 0.000 732.440 1.120 ;
  LAYER ME3 ;
  RECT 728.900 0.000 732.440 1.120 ;
  LAYER ME2 ;
  RECT 728.900 0.000 732.440 1.120 ;
  LAYER ME1 ;
  RECT 728.900 0.000 732.440 1.120 ;
 END
 PORT
  LAYER ME4 ;
  RECT 720.220 0.000 723.760 1.120 ;
  LAYER ME3 ;
  RECT 720.220 0.000 723.760 1.120 ;
  LAYER ME2 ;
  RECT 720.220 0.000 723.760 1.120 ;
  LAYER ME1 ;
  RECT 720.220 0.000 723.760 1.120 ;
 END
 PORT
  LAYER ME4 ;
  RECT 711.540 0.000 715.080 1.120 ;
  LAYER ME3 ;
  RECT 711.540 0.000 715.080 1.120 ;
  LAYER ME2 ;
  RECT 711.540 0.000 715.080 1.120 ;
  LAYER ME1 ;
  RECT 711.540 0.000 715.080 1.120 ;
 END
 PORT
  LAYER ME4 ;
  RECT 702.860 0.000 706.400 1.120 ;
  LAYER ME3 ;
  RECT 702.860 0.000 706.400 1.120 ;
  LAYER ME2 ;
  RECT 702.860 0.000 706.400 1.120 ;
  LAYER ME1 ;
  RECT 702.860 0.000 706.400 1.120 ;
 END
 PORT
  LAYER ME4 ;
  RECT 694.180 0.000 697.720 1.120 ;
  LAYER ME3 ;
  RECT 694.180 0.000 697.720 1.120 ;
  LAYER ME2 ;
  RECT 694.180 0.000 697.720 1.120 ;
  LAYER ME1 ;
  RECT 694.180 0.000 697.720 1.120 ;
 END
 PORT
  LAYER ME4 ;
  RECT 685.500 0.000 689.040 1.120 ;
  LAYER ME3 ;
  RECT 685.500 0.000 689.040 1.120 ;
  LAYER ME2 ;
  RECT 685.500 0.000 689.040 1.120 ;
  LAYER ME1 ;
  RECT 685.500 0.000 689.040 1.120 ;
 END
 PORT
  LAYER ME4 ;
  RECT 624.740 0.000 628.280 1.120 ;
  LAYER ME3 ;
  RECT 624.740 0.000 628.280 1.120 ;
  LAYER ME2 ;
  RECT 624.740 0.000 628.280 1.120 ;
  LAYER ME1 ;
  RECT 624.740 0.000 628.280 1.120 ;
 END
 PORT
  LAYER ME4 ;
  RECT 616.060 0.000 619.600 1.120 ;
  LAYER ME3 ;
  RECT 616.060 0.000 619.600 1.120 ;
  LAYER ME2 ;
  RECT 616.060 0.000 619.600 1.120 ;
  LAYER ME1 ;
  RECT 616.060 0.000 619.600 1.120 ;
 END
 PORT
  LAYER ME4 ;
  RECT 607.380 0.000 610.920 1.120 ;
  LAYER ME3 ;
  RECT 607.380 0.000 610.920 1.120 ;
  LAYER ME2 ;
  RECT 607.380 0.000 610.920 1.120 ;
  LAYER ME1 ;
  RECT 607.380 0.000 610.920 1.120 ;
 END
 PORT
  LAYER ME4 ;
  RECT 598.700 0.000 602.240 1.120 ;
  LAYER ME3 ;
  RECT 598.700 0.000 602.240 1.120 ;
  LAYER ME2 ;
  RECT 598.700 0.000 602.240 1.120 ;
  LAYER ME1 ;
  RECT 598.700 0.000 602.240 1.120 ;
 END
 PORT
  LAYER ME4 ;
  RECT 590.020 0.000 593.560 1.120 ;
  LAYER ME3 ;
  RECT 590.020 0.000 593.560 1.120 ;
  LAYER ME2 ;
  RECT 590.020 0.000 593.560 1.120 ;
  LAYER ME1 ;
  RECT 590.020 0.000 593.560 1.120 ;
 END
 PORT
  LAYER ME4 ;
  RECT 581.340 0.000 584.880 1.120 ;
  LAYER ME3 ;
  RECT 581.340 0.000 584.880 1.120 ;
  LAYER ME2 ;
  RECT 581.340 0.000 584.880 1.120 ;
  LAYER ME1 ;
  RECT 581.340 0.000 584.880 1.120 ;
 END
 PORT
  LAYER ME4 ;
  RECT 519.960 0.000 523.500 1.120 ;
  LAYER ME3 ;
  RECT 519.960 0.000 523.500 1.120 ;
  LAYER ME2 ;
  RECT 519.960 0.000 523.500 1.120 ;
  LAYER ME1 ;
  RECT 519.960 0.000 523.500 1.120 ;
 END
 PORT
  LAYER ME4 ;
  RECT 511.280 0.000 514.820 1.120 ;
  LAYER ME3 ;
  RECT 511.280 0.000 514.820 1.120 ;
  LAYER ME2 ;
  RECT 511.280 0.000 514.820 1.120 ;
  LAYER ME1 ;
  RECT 511.280 0.000 514.820 1.120 ;
 END
 PORT
  LAYER ME4 ;
  RECT 502.600 0.000 506.140 1.120 ;
  LAYER ME3 ;
  RECT 502.600 0.000 506.140 1.120 ;
  LAYER ME2 ;
  RECT 502.600 0.000 506.140 1.120 ;
  LAYER ME1 ;
  RECT 502.600 0.000 506.140 1.120 ;
 END
 PORT
  LAYER ME4 ;
  RECT 493.920 0.000 497.460 1.120 ;
  LAYER ME3 ;
  RECT 493.920 0.000 497.460 1.120 ;
  LAYER ME2 ;
  RECT 493.920 0.000 497.460 1.120 ;
  LAYER ME1 ;
  RECT 493.920 0.000 497.460 1.120 ;
 END
 PORT
  LAYER ME4 ;
  RECT 485.240 0.000 488.780 1.120 ;
  LAYER ME3 ;
  RECT 485.240 0.000 488.780 1.120 ;
  LAYER ME2 ;
  RECT 485.240 0.000 488.780 1.120 ;
  LAYER ME1 ;
  RECT 485.240 0.000 488.780 1.120 ;
 END
 PORT
  LAYER ME4 ;
  RECT 476.560 0.000 480.100 1.120 ;
  LAYER ME3 ;
  RECT 476.560 0.000 480.100 1.120 ;
  LAYER ME2 ;
  RECT 476.560 0.000 480.100 1.120 ;
  LAYER ME1 ;
  RECT 476.560 0.000 480.100 1.120 ;
 END
 PORT
  LAYER ME4 ;
  RECT 397.820 0.000 401.360 1.120 ;
  LAYER ME3 ;
  RECT 397.820 0.000 401.360 1.120 ;
  LAYER ME2 ;
  RECT 397.820 0.000 401.360 1.120 ;
  LAYER ME1 ;
  RECT 397.820 0.000 401.360 1.120 ;
 END
 PORT
  LAYER ME4 ;
  RECT 369.920 0.000 373.460 1.120 ;
  LAYER ME3 ;
  RECT 369.920 0.000 373.460 1.120 ;
  LAYER ME2 ;
  RECT 369.920 0.000 373.460 1.120 ;
  LAYER ME1 ;
  RECT 369.920 0.000 373.460 1.120 ;
 END
 PORT
  LAYER ME4 ;
  RECT 348.220 0.000 351.760 1.120 ;
  LAYER ME3 ;
  RECT 348.220 0.000 351.760 1.120 ;
  LAYER ME2 ;
  RECT 348.220 0.000 351.760 1.120 ;
  LAYER ME1 ;
  RECT 348.220 0.000 351.760 1.120 ;
 END
 PORT
  LAYER ME4 ;
  RECT 339.540 0.000 343.080 1.120 ;
  LAYER ME3 ;
  RECT 339.540 0.000 343.080 1.120 ;
  LAYER ME2 ;
  RECT 339.540 0.000 343.080 1.120 ;
  LAYER ME1 ;
  RECT 339.540 0.000 343.080 1.120 ;
 END
 PORT
  LAYER ME4 ;
  RECT 330.860 0.000 334.400 1.120 ;
  LAYER ME3 ;
  RECT 330.860 0.000 334.400 1.120 ;
  LAYER ME2 ;
  RECT 330.860 0.000 334.400 1.120 ;
  LAYER ME1 ;
  RECT 330.860 0.000 334.400 1.120 ;
 END
 PORT
  LAYER ME4 ;
  RECT 322.180 0.000 325.720 1.120 ;
  LAYER ME3 ;
  RECT 322.180 0.000 325.720 1.120 ;
  LAYER ME2 ;
  RECT 322.180 0.000 325.720 1.120 ;
  LAYER ME1 ;
  RECT 322.180 0.000 325.720 1.120 ;
 END
 PORT
  LAYER ME4 ;
  RECT 278.780 0.000 282.320 1.120 ;
  LAYER ME3 ;
  RECT 278.780 0.000 282.320 1.120 ;
  LAYER ME2 ;
  RECT 278.780 0.000 282.320 1.120 ;
  LAYER ME1 ;
  RECT 278.780 0.000 282.320 1.120 ;
 END
 PORT
  LAYER ME4 ;
  RECT 270.100 0.000 273.640 1.120 ;
  LAYER ME3 ;
  RECT 270.100 0.000 273.640 1.120 ;
  LAYER ME2 ;
  RECT 270.100 0.000 273.640 1.120 ;
  LAYER ME1 ;
  RECT 270.100 0.000 273.640 1.120 ;
 END
 PORT
  LAYER ME4 ;
  RECT 261.420 0.000 264.960 1.120 ;
  LAYER ME3 ;
  RECT 261.420 0.000 264.960 1.120 ;
  LAYER ME2 ;
  RECT 261.420 0.000 264.960 1.120 ;
  LAYER ME1 ;
  RECT 261.420 0.000 264.960 1.120 ;
 END
 PORT
  LAYER ME4 ;
  RECT 239.720 0.000 243.260 1.120 ;
  LAYER ME3 ;
  RECT 239.720 0.000 243.260 1.120 ;
  LAYER ME2 ;
  RECT 239.720 0.000 243.260 1.120 ;
  LAYER ME1 ;
  RECT 239.720 0.000 243.260 1.120 ;
 END
 PORT
  LAYER ME4 ;
  RECT 226.700 0.000 230.240 1.120 ;
  LAYER ME3 ;
  RECT 226.700 0.000 230.240 1.120 ;
  LAYER ME2 ;
  RECT 226.700 0.000 230.240 1.120 ;
  LAYER ME1 ;
  RECT 226.700 0.000 230.240 1.120 ;
 END
 PORT
  LAYER ME4 ;
  RECT 218.020 0.000 221.560 1.120 ;
  LAYER ME3 ;
  RECT 218.020 0.000 221.560 1.120 ;
  LAYER ME2 ;
  RECT 218.020 0.000 221.560 1.120 ;
  LAYER ME1 ;
  RECT 218.020 0.000 221.560 1.120 ;
 END
 PORT
  LAYER ME4 ;
  RECT 174.620 0.000 178.160 1.120 ;
  LAYER ME3 ;
  RECT 174.620 0.000 178.160 1.120 ;
  LAYER ME2 ;
  RECT 174.620 0.000 178.160 1.120 ;
  LAYER ME1 ;
  RECT 174.620 0.000 178.160 1.120 ;
 END
 PORT
  LAYER ME4 ;
  RECT 165.940 0.000 169.480 1.120 ;
  LAYER ME3 ;
  RECT 165.940 0.000 169.480 1.120 ;
  LAYER ME2 ;
  RECT 165.940 0.000 169.480 1.120 ;
  LAYER ME1 ;
  RECT 165.940 0.000 169.480 1.120 ;
 END
 PORT
  LAYER ME4 ;
  RECT 157.260 0.000 160.800 1.120 ;
  LAYER ME3 ;
  RECT 157.260 0.000 160.800 1.120 ;
  LAYER ME2 ;
  RECT 157.260 0.000 160.800 1.120 ;
  LAYER ME1 ;
  RECT 157.260 0.000 160.800 1.120 ;
 END
 PORT
  LAYER ME4 ;
  RECT 148.580 0.000 152.120 1.120 ;
  LAYER ME3 ;
  RECT 148.580 0.000 152.120 1.120 ;
  LAYER ME2 ;
  RECT 148.580 0.000 152.120 1.120 ;
  LAYER ME1 ;
  RECT 148.580 0.000 152.120 1.120 ;
 END
 PORT
  LAYER ME4 ;
  RECT 126.880 0.000 130.420 1.120 ;
  LAYER ME3 ;
  RECT 126.880 0.000 130.420 1.120 ;
  LAYER ME2 ;
  RECT 126.880 0.000 130.420 1.120 ;
  LAYER ME1 ;
  RECT 126.880 0.000 130.420 1.120 ;
 END
 PORT
  LAYER ME4 ;
  RECT 113.860 0.000 117.400 1.120 ;
  LAYER ME3 ;
  RECT 113.860 0.000 117.400 1.120 ;
  LAYER ME2 ;
  RECT 113.860 0.000 117.400 1.120 ;
  LAYER ME1 ;
  RECT 113.860 0.000 117.400 1.120 ;
 END
 PORT
  LAYER ME4 ;
  RECT 70.460 0.000 74.000 1.120 ;
  LAYER ME3 ;
  RECT 70.460 0.000 74.000 1.120 ;
  LAYER ME2 ;
  RECT 70.460 0.000 74.000 1.120 ;
  LAYER ME1 ;
  RECT 70.460 0.000 74.000 1.120 ;
 END
 PORT
  LAYER ME4 ;
  RECT 61.780 0.000 65.320 1.120 ;
  LAYER ME3 ;
  RECT 61.780 0.000 65.320 1.120 ;
  LAYER ME2 ;
  RECT 61.780 0.000 65.320 1.120 ;
  LAYER ME1 ;
  RECT 61.780 0.000 65.320 1.120 ;
 END
 PORT
  LAYER ME4 ;
  RECT 53.100 0.000 56.640 1.120 ;
  LAYER ME3 ;
  RECT 53.100 0.000 56.640 1.120 ;
  LAYER ME2 ;
  RECT 53.100 0.000 56.640 1.120 ;
  LAYER ME1 ;
  RECT 53.100 0.000 56.640 1.120 ;
 END
 PORT
  LAYER ME4 ;
  RECT 44.420 0.000 47.960 1.120 ;
  LAYER ME3 ;
  RECT 44.420 0.000 47.960 1.120 ;
  LAYER ME2 ;
  RECT 44.420 0.000 47.960 1.120 ;
  LAYER ME1 ;
  RECT 44.420 0.000 47.960 1.120 ;
 END
 PORT
  LAYER ME4 ;
  RECT 35.740 0.000 39.280 1.120 ;
  LAYER ME3 ;
  RECT 35.740 0.000 39.280 1.120 ;
  LAYER ME2 ;
  RECT 35.740 0.000 39.280 1.120 ;
  LAYER ME1 ;
  RECT 35.740 0.000 39.280 1.120 ;
 END
 PORT
  LAYER ME4 ;
  RECT 14.040 0.000 17.580 1.120 ;
  LAYER ME3 ;
  RECT 14.040 0.000 17.580 1.120 ;
  LAYER ME2 ;
  RECT 14.040 0.000 17.580 1.120 ;
  LAYER ME1 ;
  RECT 14.040 0.000 17.580 1.120 ;
 END
END VCC
PIN GND
  DIRECTION INOUT ;
  USE GROUND ;
  SHAPE ABUTMENT ;
 PORT
  LAYER ME4 ;
  RECT 777.600 435.460 778.720 438.700 ;
  LAYER ME3 ;
  RECT 777.600 435.460 778.720 438.700 ;
  LAYER ME2 ;
  RECT 777.600 435.460 778.720 438.700 ;
  LAYER ME1 ;
  RECT 777.600 435.460 778.720 438.700 ;
 END
 PORT
  LAYER ME4 ;
  RECT 777.600 427.620 778.720 430.860 ;
  LAYER ME3 ;
  RECT 777.600 427.620 778.720 430.860 ;
  LAYER ME2 ;
  RECT 777.600 427.620 778.720 430.860 ;
  LAYER ME1 ;
  RECT 777.600 427.620 778.720 430.860 ;
 END
 PORT
  LAYER ME4 ;
  RECT 777.600 419.780 778.720 423.020 ;
  LAYER ME3 ;
  RECT 777.600 419.780 778.720 423.020 ;
  LAYER ME2 ;
  RECT 777.600 419.780 778.720 423.020 ;
  LAYER ME1 ;
  RECT 777.600 419.780 778.720 423.020 ;
 END
 PORT
  LAYER ME4 ;
  RECT 777.600 411.940 778.720 415.180 ;
  LAYER ME3 ;
  RECT 777.600 411.940 778.720 415.180 ;
  LAYER ME2 ;
  RECT 777.600 411.940 778.720 415.180 ;
  LAYER ME1 ;
  RECT 777.600 411.940 778.720 415.180 ;
 END
 PORT
  LAYER ME4 ;
  RECT 777.600 404.100 778.720 407.340 ;
  LAYER ME3 ;
  RECT 777.600 404.100 778.720 407.340 ;
  LAYER ME2 ;
  RECT 777.600 404.100 778.720 407.340 ;
  LAYER ME1 ;
  RECT 777.600 404.100 778.720 407.340 ;
 END
 PORT
  LAYER ME4 ;
  RECT 777.600 364.900 778.720 368.140 ;
  LAYER ME3 ;
  RECT 777.600 364.900 778.720 368.140 ;
  LAYER ME2 ;
  RECT 777.600 364.900 778.720 368.140 ;
  LAYER ME1 ;
  RECT 777.600 364.900 778.720 368.140 ;
 END
 PORT
  LAYER ME4 ;
  RECT 777.600 357.060 778.720 360.300 ;
  LAYER ME3 ;
  RECT 777.600 357.060 778.720 360.300 ;
  LAYER ME2 ;
  RECT 777.600 357.060 778.720 360.300 ;
  LAYER ME1 ;
  RECT 777.600 357.060 778.720 360.300 ;
 END
 PORT
  LAYER ME4 ;
  RECT 777.600 349.220 778.720 352.460 ;
  LAYER ME3 ;
  RECT 777.600 349.220 778.720 352.460 ;
  LAYER ME2 ;
  RECT 777.600 349.220 778.720 352.460 ;
  LAYER ME1 ;
  RECT 777.600 349.220 778.720 352.460 ;
 END
 PORT
  LAYER ME4 ;
  RECT 777.600 341.380 778.720 344.620 ;
  LAYER ME3 ;
  RECT 777.600 341.380 778.720 344.620 ;
  LAYER ME2 ;
  RECT 777.600 341.380 778.720 344.620 ;
  LAYER ME1 ;
  RECT 777.600 341.380 778.720 344.620 ;
 END
 PORT
  LAYER ME4 ;
  RECT 777.600 333.540 778.720 336.780 ;
  LAYER ME3 ;
  RECT 777.600 333.540 778.720 336.780 ;
  LAYER ME2 ;
  RECT 777.600 333.540 778.720 336.780 ;
  LAYER ME1 ;
  RECT 777.600 333.540 778.720 336.780 ;
 END
 PORT
  LAYER ME4 ;
  RECT 777.600 325.700 778.720 328.940 ;
  LAYER ME3 ;
  RECT 777.600 325.700 778.720 328.940 ;
  LAYER ME2 ;
  RECT 777.600 325.700 778.720 328.940 ;
  LAYER ME1 ;
  RECT 777.600 325.700 778.720 328.940 ;
 END
 PORT
  LAYER ME4 ;
  RECT 777.600 286.500 778.720 289.740 ;
  LAYER ME3 ;
  RECT 777.600 286.500 778.720 289.740 ;
  LAYER ME2 ;
  RECT 777.600 286.500 778.720 289.740 ;
  LAYER ME1 ;
  RECT 777.600 286.500 778.720 289.740 ;
 END
 PORT
  LAYER ME4 ;
  RECT 777.600 278.660 778.720 281.900 ;
  LAYER ME3 ;
  RECT 777.600 278.660 778.720 281.900 ;
  LAYER ME2 ;
  RECT 777.600 278.660 778.720 281.900 ;
  LAYER ME1 ;
  RECT 777.600 278.660 778.720 281.900 ;
 END
 PORT
  LAYER ME4 ;
  RECT 777.600 270.820 778.720 274.060 ;
  LAYER ME3 ;
  RECT 777.600 270.820 778.720 274.060 ;
  LAYER ME2 ;
  RECT 777.600 270.820 778.720 274.060 ;
  LAYER ME1 ;
  RECT 777.600 270.820 778.720 274.060 ;
 END
 PORT
  LAYER ME4 ;
  RECT 777.600 262.980 778.720 266.220 ;
  LAYER ME3 ;
  RECT 777.600 262.980 778.720 266.220 ;
  LAYER ME2 ;
  RECT 777.600 262.980 778.720 266.220 ;
  LAYER ME1 ;
  RECT 777.600 262.980 778.720 266.220 ;
 END
 PORT
  LAYER ME4 ;
  RECT 777.600 255.140 778.720 258.380 ;
  LAYER ME3 ;
  RECT 777.600 255.140 778.720 258.380 ;
  LAYER ME2 ;
  RECT 777.600 255.140 778.720 258.380 ;
  LAYER ME1 ;
  RECT 777.600 255.140 778.720 258.380 ;
 END
 PORT
  LAYER ME4 ;
  RECT 777.600 247.300 778.720 250.540 ;
  LAYER ME3 ;
  RECT 777.600 247.300 778.720 250.540 ;
  LAYER ME2 ;
  RECT 777.600 247.300 778.720 250.540 ;
  LAYER ME1 ;
  RECT 777.600 247.300 778.720 250.540 ;
 END
 PORT
  LAYER ME4 ;
  RECT 777.600 208.100 778.720 211.340 ;
  LAYER ME3 ;
  RECT 777.600 208.100 778.720 211.340 ;
  LAYER ME2 ;
  RECT 777.600 208.100 778.720 211.340 ;
  LAYER ME1 ;
  RECT 777.600 208.100 778.720 211.340 ;
 END
 PORT
  LAYER ME4 ;
  RECT 777.600 200.260 778.720 203.500 ;
  LAYER ME3 ;
  RECT 777.600 200.260 778.720 203.500 ;
  LAYER ME2 ;
  RECT 777.600 200.260 778.720 203.500 ;
  LAYER ME1 ;
  RECT 777.600 200.260 778.720 203.500 ;
 END
 PORT
  LAYER ME4 ;
  RECT 777.600 192.420 778.720 195.660 ;
  LAYER ME3 ;
  RECT 777.600 192.420 778.720 195.660 ;
  LAYER ME2 ;
  RECT 777.600 192.420 778.720 195.660 ;
  LAYER ME1 ;
  RECT 777.600 192.420 778.720 195.660 ;
 END
 PORT
  LAYER ME4 ;
  RECT 777.600 184.580 778.720 187.820 ;
  LAYER ME3 ;
  RECT 777.600 184.580 778.720 187.820 ;
  LAYER ME2 ;
  RECT 777.600 184.580 778.720 187.820 ;
  LAYER ME1 ;
  RECT 777.600 184.580 778.720 187.820 ;
 END
 PORT
  LAYER ME4 ;
  RECT 777.600 176.740 778.720 179.980 ;
  LAYER ME3 ;
  RECT 777.600 176.740 778.720 179.980 ;
  LAYER ME2 ;
  RECT 777.600 176.740 778.720 179.980 ;
  LAYER ME1 ;
  RECT 777.600 176.740 778.720 179.980 ;
 END
 PORT
  LAYER ME4 ;
  RECT 777.600 168.900 778.720 172.140 ;
  LAYER ME3 ;
  RECT 777.600 168.900 778.720 172.140 ;
  LAYER ME2 ;
  RECT 777.600 168.900 778.720 172.140 ;
  LAYER ME1 ;
  RECT 777.600 168.900 778.720 172.140 ;
 END
 PORT
  LAYER ME4 ;
  RECT 777.600 129.700 778.720 132.940 ;
  LAYER ME3 ;
  RECT 777.600 129.700 778.720 132.940 ;
  LAYER ME2 ;
  RECT 777.600 129.700 778.720 132.940 ;
  LAYER ME1 ;
  RECT 777.600 129.700 778.720 132.940 ;
 END
 PORT
  LAYER ME4 ;
  RECT 777.600 121.860 778.720 125.100 ;
  LAYER ME3 ;
  RECT 777.600 121.860 778.720 125.100 ;
  LAYER ME2 ;
  RECT 777.600 121.860 778.720 125.100 ;
  LAYER ME1 ;
  RECT 777.600 121.860 778.720 125.100 ;
 END
 PORT
  LAYER ME4 ;
  RECT 777.600 114.020 778.720 117.260 ;
  LAYER ME3 ;
  RECT 777.600 114.020 778.720 117.260 ;
  LAYER ME2 ;
  RECT 777.600 114.020 778.720 117.260 ;
  LAYER ME1 ;
  RECT 777.600 114.020 778.720 117.260 ;
 END
 PORT
  LAYER ME4 ;
  RECT 777.600 106.180 778.720 109.420 ;
  LAYER ME3 ;
  RECT 777.600 106.180 778.720 109.420 ;
  LAYER ME2 ;
  RECT 777.600 106.180 778.720 109.420 ;
  LAYER ME1 ;
  RECT 777.600 106.180 778.720 109.420 ;
 END
 PORT
  LAYER ME4 ;
  RECT 777.600 98.340 778.720 101.580 ;
  LAYER ME3 ;
  RECT 777.600 98.340 778.720 101.580 ;
  LAYER ME2 ;
  RECT 777.600 98.340 778.720 101.580 ;
  LAYER ME1 ;
  RECT 777.600 98.340 778.720 101.580 ;
 END
 PORT
  LAYER ME4 ;
  RECT 777.600 90.500 778.720 93.740 ;
  LAYER ME3 ;
  RECT 777.600 90.500 778.720 93.740 ;
  LAYER ME2 ;
  RECT 777.600 90.500 778.720 93.740 ;
  LAYER ME1 ;
  RECT 777.600 90.500 778.720 93.740 ;
 END
 PORT
  LAYER ME4 ;
  RECT 777.600 51.300 778.720 54.540 ;
  LAYER ME3 ;
  RECT 777.600 51.300 778.720 54.540 ;
  LAYER ME2 ;
  RECT 777.600 51.300 778.720 54.540 ;
  LAYER ME1 ;
  RECT 777.600 51.300 778.720 54.540 ;
 END
 PORT
  LAYER ME4 ;
  RECT 777.600 43.460 778.720 46.700 ;
  LAYER ME3 ;
  RECT 777.600 43.460 778.720 46.700 ;
  LAYER ME2 ;
  RECT 777.600 43.460 778.720 46.700 ;
  LAYER ME1 ;
  RECT 777.600 43.460 778.720 46.700 ;
 END
 PORT
  LAYER ME4 ;
  RECT 777.600 35.620 778.720 38.860 ;
  LAYER ME3 ;
  RECT 777.600 35.620 778.720 38.860 ;
  LAYER ME2 ;
  RECT 777.600 35.620 778.720 38.860 ;
  LAYER ME1 ;
  RECT 777.600 35.620 778.720 38.860 ;
 END
 PORT
  LAYER ME4 ;
  RECT 777.600 27.780 778.720 31.020 ;
  LAYER ME3 ;
  RECT 777.600 27.780 778.720 31.020 ;
  LAYER ME2 ;
  RECT 777.600 27.780 778.720 31.020 ;
  LAYER ME1 ;
  RECT 777.600 27.780 778.720 31.020 ;
 END
 PORT
  LAYER ME4 ;
  RECT 777.600 19.940 778.720 23.180 ;
  LAYER ME3 ;
  RECT 777.600 19.940 778.720 23.180 ;
  LAYER ME2 ;
  RECT 777.600 19.940 778.720 23.180 ;
  LAYER ME1 ;
  RECT 777.600 19.940 778.720 23.180 ;
 END
 PORT
  LAYER ME4 ;
  RECT 777.600 12.100 778.720 15.340 ;
  LAYER ME3 ;
  RECT 777.600 12.100 778.720 15.340 ;
  LAYER ME2 ;
  RECT 777.600 12.100 778.720 15.340 ;
  LAYER ME1 ;
  RECT 777.600 12.100 778.720 15.340 ;
 END
 PORT
  LAYER ME4 ;
  RECT 0.000 435.460 1.120 438.700 ;
  LAYER ME3 ;
  RECT 0.000 435.460 1.120 438.700 ;
  LAYER ME2 ;
  RECT 0.000 435.460 1.120 438.700 ;
  LAYER ME1 ;
  RECT 0.000 435.460 1.120 438.700 ;
 END
 PORT
  LAYER ME4 ;
  RECT 0.000 427.620 1.120 430.860 ;
  LAYER ME3 ;
  RECT 0.000 427.620 1.120 430.860 ;
  LAYER ME2 ;
  RECT 0.000 427.620 1.120 430.860 ;
  LAYER ME1 ;
  RECT 0.000 427.620 1.120 430.860 ;
 END
 PORT
  LAYER ME4 ;
  RECT 0.000 419.780 1.120 423.020 ;
  LAYER ME3 ;
  RECT 0.000 419.780 1.120 423.020 ;
  LAYER ME2 ;
  RECT 0.000 419.780 1.120 423.020 ;
  LAYER ME1 ;
  RECT 0.000 419.780 1.120 423.020 ;
 END
 PORT
  LAYER ME4 ;
  RECT 0.000 411.940 1.120 415.180 ;
  LAYER ME3 ;
  RECT 0.000 411.940 1.120 415.180 ;
  LAYER ME2 ;
  RECT 0.000 411.940 1.120 415.180 ;
  LAYER ME1 ;
  RECT 0.000 411.940 1.120 415.180 ;
 END
 PORT
  LAYER ME4 ;
  RECT 0.000 404.100 1.120 407.340 ;
  LAYER ME3 ;
  RECT 0.000 404.100 1.120 407.340 ;
  LAYER ME2 ;
  RECT 0.000 404.100 1.120 407.340 ;
  LAYER ME1 ;
  RECT 0.000 404.100 1.120 407.340 ;
 END
 PORT
  LAYER ME4 ;
  RECT 0.000 364.900 1.120 368.140 ;
  LAYER ME3 ;
  RECT 0.000 364.900 1.120 368.140 ;
  LAYER ME2 ;
  RECT 0.000 364.900 1.120 368.140 ;
  LAYER ME1 ;
  RECT 0.000 364.900 1.120 368.140 ;
 END
 PORT
  LAYER ME4 ;
  RECT 0.000 357.060 1.120 360.300 ;
  LAYER ME3 ;
  RECT 0.000 357.060 1.120 360.300 ;
  LAYER ME2 ;
  RECT 0.000 357.060 1.120 360.300 ;
  LAYER ME1 ;
  RECT 0.000 357.060 1.120 360.300 ;
 END
 PORT
  LAYER ME4 ;
  RECT 0.000 349.220 1.120 352.460 ;
  LAYER ME3 ;
  RECT 0.000 349.220 1.120 352.460 ;
  LAYER ME2 ;
  RECT 0.000 349.220 1.120 352.460 ;
  LAYER ME1 ;
  RECT 0.000 349.220 1.120 352.460 ;
 END
 PORT
  LAYER ME4 ;
  RECT 0.000 341.380 1.120 344.620 ;
  LAYER ME3 ;
  RECT 0.000 341.380 1.120 344.620 ;
  LAYER ME2 ;
  RECT 0.000 341.380 1.120 344.620 ;
  LAYER ME1 ;
  RECT 0.000 341.380 1.120 344.620 ;
 END
 PORT
  LAYER ME4 ;
  RECT 0.000 333.540 1.120 336.780 ;
  LAYER ME3 ;
  RECT 0.000 333.540 1.120 336.780 ;
  LAYER ME2 ;
  RECT 0.000 333.540 1.120 336.780 ;
  LAYER ME1 ;
  RECT 0.000 333.540 1.120 336.780 ;
 END
 PORT
  LAYER ME4 ;
  RECT 0.000 325.700 1.120 328.940 ;
  LAYER ME3 ;
  RECT 0.000 325.700 1.120 328.940 ;
  LAYER ME2 ;
  RECT 0.000 325.700 1.120 328.940 ;
  LAYER ME1 ;
  RECT 0.000 325.700 1.120 328.940 ;
 END
 PORT
  LAYER ME4 ;
  RECT 0.000 286.500 1.120 289.740 ;
  LAYER ME3 ;
  RECT 0.000 286.500 1.120 289.740 ;
  LAYER ME2 ;
  RECT 0.000 286.500 1.120 289.740 ;
  LAYER ME1 ;
  RECT 0.000 286.500 1.120 289.740 ;
 END
 PORT
  LAYER ME4 ;
  RECT 0.000 278.660 1.120 281.900 ;
  LAYER ME3 ;
  RECT 0.000 278.660 1.120 281.900 ;
  LAYER ME2 ;
  RECT 0.000 278.660 1.120 281.900 ;
  LAYER ME1 ;
  RECT 0.000 278.660 1.120 281.900 ;
 END
 PORT
  LAYER ME4 ;
  RECT 0.000 270.820 1.120 274.060 ;
  LAYER ME3 ;
  RECT 0.000 270.820 1.120 274.060 ;
  LAYER ME2 ;
  RECT 0.000 270.820 1.120 274.060 ;
  LAYER ME1 ;
  RECT 0.000 270.820 1.120 274.060 ;
 END
 PORT
  LAYER ME4 ;
  RECT 0.000 262.980 1.120 266.220 ;
  LAYER ME3 ;
  RECT 0.000 262.980 1.120 266.220 ;
  LAYER ME2 ;
  RECT 0.000 262.980 1.120 266.220 ;
  LAYER ME1 ;
  RECT 0.000 262.980 1.120 266.220 ;
 END
 PORT
  LAYER ME4 ;
  RECT 0.000 255.140 1.120 258.380 ;
  LAYER ME3 ;
  RECT 0.000 255.140 1.120 258.380 ;
  LAYER ME2 ;
  RECT 0.000 255.140 1.120 258.380 ;
  LAYER ME1 ;
  RECT 0.000 255.140 1.120 258.380 ;
 END
 PORT
  LAYER ME4 ;
  RECT 0.000 247.300 1.120 250.540 ;
  LAYER ME3 ;
  RECT 0.000 247.300 1.120 250.540 ;
  LAYER ME2 ;
  RECT 0.000 247.300 1.120 250.540 ;
  LAYER ME1 ;
  RECT 0.000 247.300 1.120 250.540 ;
 END
 PORT
  LAYER ME4 ;
  RECT 0.000 208.100 1.120 211.340 ;
  LAYER ME3 ;
  RECT 0.000 208.100 1.120 211.340 ;
  LAYER ME2 ;
  RECT 0.000 208.100 1.120 211.340 ;
  LAYER ME1 ;
  RECT 0.000 208.100 1.120 211.340 ;
 END
 PORT
  LAYER ME4 ;
  RECT 0.000 200.260 1.120 203.500 ;
  LAYER ME3 ;
  RECT 0.000 200.260 1.120 203.500 ;
  LAYER ME2 ;
  RECT 0.000 200.260 1.120 203.500 ;
  LAYER ME1 ;
  RECT 0.000 200.260 1.120 203.500 ;
 END
 PORT
  LAYER ME4 ;
  RECT 0.000 192.420 1.120 195.660 ;
  LAYER ME3 ;
  RECT 0.000 192.420 1.120 195.660 ;
  LAYER ME2 ;
  RECT 0.000 192.420 1.120 195.660 ;
  LAYER ME1 ;
  RECT 0.000 192.420 1.120 195.660 ;
 END
 PORT
  LAYER ME4 ;
  RECT 0.000 184.580 1.120 187.820 ;
  LAYER ME3 ;
  RECT 0.000 184.580 1.120 187.820 ;
  LAYER ME2 ;
  RECT 0.000 184.580 1.120 187.820 ;
  LAYER ME1 ;
  RECT 0.000 184.580 1.120 187.820 ;
 END
 PORT
  LAYER ME4 ;
  RECT 0.000 176.740 1.120 179.980 ;
  LAYER ME3 ;
  RECT 0.000 176.740 1.120 179.980 ;
  LAYER ME2 ;
  RECT 0.000 176.740 1.120 179.980 ;
  LAYER ME1 ;
  RECT 0.000 176.740 1.120 179.980 ;
 END
 PORT
  LAYER ME4 ;
  RECT 0.000 168.900 1.120 172.140 ;
  LAYER ME3 ;
  RECT 0.000 168.900 1.120 172.140 ;
  LAYER ME2 ;
  RECT 0.000 168.900 1.120 172.140 ;
  LAYER ME1 ;
  RECT 0.000 168.900 1.120 172.140 ;
 END
 PORT
  LAYER ME4 ;
  RECT 0.000 129.700 1.120 132.940 ;
  LAYER ME3 ;
  RECT 0.000 129.700 1.120 132.940 ;
  LAYER ME2 ;
  RECT 0.000 129.700 1.120 132.940 ;
  LAYER ME1 ;
  RECT 0.000 129.700 1.120 132.940 ;
 END
 PORT
  LAYER ME4 ;
  RECT 0.000 121.860 1.120 125.100 ;
  LAYER ME3 ;
  RECT 0.000 121.860 1.120 125.100 ;
  LAYER ME2 ;
  RECT 0.000 121.860 1.120 125.100 ;
  LAYER ME1 ;
  RECT 0.000 121.860 1.120 125.100 ;
 END
 PORT
  LAYER ME4 ;
  RECT 0.000 114.020 1.120 117.260 ;
  LAYER ME3 ;
  RECT 0.000 114.020 1.120 117.260 ;
  LAYER ME2 ;
  RECT 0.000 114.020 1.120 117.260 ;
  LAYER ME1 ;
  RECT 0.000 114.020 1.120 117.260 ;
 END
 PORT
  LAYER ME4 ;
  RECT 0.000 106.180 1.120 109.420 ;
  LAYER ME3 ;
  RECT 0.000 106.180 1.120 109.420 ;
  LAYER ME2 ;
  RECT 0.000 106.180 1.120 109.420 ;
  LAYER ME1 ;
  RECT 0.000 106.180 1.120 109.420 ;
 END
 PORT
  LAYER ME4 ;
  RECT 0.000 98.340 1.120 101.580 ;
  LAYER ME3 ;
  RECT 0.000 98.340 1.120 101.580 ;
  LAYER ME2 ;
  RECT 0.000 98.340 1.120 101.580 ;
  LAYER ME1 ;
  RECT 0.000 98.340 1.120 101.580 ;
 END
 PORT
  LAYER ME4 ;
  RECT 0.000 90.500 1.120 93.740 ;
  LAYER ME3 ;
  RECT 0.000 90.500 1.120 93.740 ;
  LAYER ME2 ;
  RECT 0.000 90.500 1.120 93.740 ;
  LAYER ME1 ;
  RECT 0.000 90.500 1.120 93.740 ;
 END
 PORT
  LAYER ME4 ;
  RECT 0.000 51.300 1.120 54.540 ;
  LAYER ME3 ;
  RECT 0.000 51.300 1.120 54.540 ;
  LAYER ME2 ;
  RECT 0.000 51.300 1.120 54.540 ;
  LAYER ME1 ;
  RECT 0.000 51.300 1.120 54.540 ;
 END
 PORT
  LAYER ME4 ;
  RECT 0.000 43.460 1.120 46.700 ;
  LAYER ME3 ;
  RECT 0.000 43.460 1.120 46.700 ;
  LAYER ME2 ;
  RECT 0.000 43.460 1.120 46.700 ;
  LAYER ME1 ;
  RECT 0.000 43.460 1.120 46.700 ;
 END
 PORT
  LAYER ME4 ;
  RECT 0.000 35.620 1.120 38.860 ;
  LAYER ME3 ;
  RECT 0.000 35.620 1.120 38.860 ;
  LAYER ME2 ;
  RECT 0.000 35.620 1.120 38.860 ;
  LAYER ME1 ;
  RECT 0.000 35.620 1.120 38.860 ;
 END
 PORT
  LAYER ME4 ;
  RECT 0.000 27.780 1.120 31.020 ;
  LAYER ME3 ;
  RECT 0.000 27.780 1.120 31.020 ;
  LAYER ME2 ;
  RECT 0.000 27.780 1.120 31.020 ;
  LAYER ME1 ;
  RECT 0.000 27.780 1.120 31.020 ;
 END
 PORT
  LAYER ME4 ;
  RECT 0.000 19.940 1.120 23.180 ;
  LAYER ME3 ;
  RECT 0.000 19.940 1.120 23.180 ;
  LAYER ME2 ;
  RECT 0.000 19.940 1.120 23.180 ;
  LAYER ME1 ;
  RECT 0.000 19.940 1.120 23.180 ;
 END
 PORT
  LAYER ME4 ;
  RECT 0.000 12.100 1.120 15.340 ;
  LAYER ME3 ;
  RECT 0.000 12.100 1.120 15.340 ;
  LAYER ME2 ;
  RECT 0.000 12.100 1.120 15.340 ;
  LAYER ME1 ;
  RECT 0.000 12.100 1.120 15.340 ;
 END
 PORT
  LAYER ME4 ;
  RECT 749.980 449.680 753.520 450.800 ;
  LAYER ME3 ;
  RECT 749.980 449.680 753.520 450.800 ;
  LAYER ME2 ;
  RECT 749.980 449.680 753.520 450.800 ;
  LAYER ME1 ;
  RECT 749.980 449.680 753.520 450.800 ;
 END
 PORT
  LAYER ME4 ;
  RECT 741.300 449.680 744.840 450.800 ;
  LAYER ME3 ;
  RECT 741.300 449.680 744.840 450.800 ;
  LAYER ME2 ;
  RECT 741.300 449.680 744.840 450.800 ;
  LAYER ME1 ;
  RECT 741.300 449.680 744.840 450.800 ;
 END
 PORT
  LAYER ME4 ;
  RECT 732.620 449.680 736.160 450.800 ;
  LAYER ME3 ;
  RECT 732.620 449.680 736.160 450.800 ;
  LAYER ME2 ;
  RECT 732.620 449.680 736.160 450.800 ;
  LAYER ME1 ;
  RECT 732.620 449.680 736.160 450.800 ;
 END
 PORT
  LAYER ME4 ;
  RECT 723.940 449.680 727.480 450.800 ;
  LAYER ME3 ;
  RECT 723.940 449.680 727.480 450.800 ;
  LAYER ME2 ;
  RECT 723.940 449.680 727.480 450.800 ;
  LAYER ME1 ;
  RECT 723.940 449.680 727.480 450.800 ;
 END
 PORT
  LAYER ME4 ;
  RECT 715.260 449.680 718.800 450.800 ;
  LAYER ME3 ;
  RECT 715.260 449.680 718.800 450.800 ;
  LAYER ME2 ;
  RECT 715.260 449.680 718.800 450.800 ;
  LAYER ME1 ;
  RECT 715.260 449.680 718.800 450.800 ;
 END
 PORT
  LAYER ME4 ;
  RECT 706.580 449.680 710.120 450.800 ;
  LAYER ME3 ;
  RECT 706.580 449.680 710.120 450.800 ;
  LAYER ME2 ;
  RECT 706.580 449.680 710.120 450.800 ;
  LAYER ME1 ;
  RECT 706.580 449.680 710.120 450.800 ;
 END
 PORT
  LAYER ME4 ;
  RECT 663.180 449.680 666.720 450.800 ;
  LAYER ME3 ;
  RECT 663.180 449.680 666.720 450.800 ;
  LAYER ME2 ;
  RECT 663.180 449.680 666.720 450.800 ;
  LAYER ME1 ;
  RECT 663.180 449.680 666.720 450.800 ;
 END
 PORT
  LAYER ME4 ;
  RECT 654.500 449.680 658.040 450.800 ;
  LAYER ME3 ;
  RECT 654.500 449.680 658.040 450.800 ;
  LAYER ME2 ;
  RECT 654.500 449.680 658.040 450.800 ;
  LAYER ME1 ;
  RECT 654.500 449.680 658.040 450.800 ;
 END
 PORT
  LAYER ME4 ;
  RECT 645.820 449.680 649.360 450.800 ;
  LAYER ME3 ;
  RECT 645.820 449.680 649.360 450.800 ;
  LAYER ME2 ;
  RECT 645.820 449.680 649.360 450.800 ;
  LAYER ME1 ;
  RECT 645.820 449.680 649.360 450.800 ;
 END
 PORT
  LAYER ME4 ;
  RECT 637.140 449.680 640.680 450.800 ;
  LAYER ME3 ;
  RECT 637.140 449.680 640.680 450.800 ;
  LAYER ME2 ;
  RECT 637.140 449.680 640.680 450.800 ;
  LAYER ME1 ;
  RECT 637.140 449.680 640.680 450.800 ;
 END
 PORT
  LAYER ME4 ;
  RECT 628.460 449.680 632.000 450.800 ;
  LAYER ME3 ;
  RECT 628.460 449.680 632.000 450.800 ;
  LAYER ME2 ;
  RECT 628.460 449.680 632.000 450.800 ;
  LAYER ME1 ;
  RECT 628.460 449.680 632.000 450.800 ;
 END
 PORT
  LAYER ME4 ;
  RECT 619.780 449.680 623.320 450.800 ;
  LAYER ME3 ;
  RECT 619.780 449.680 623.320 450.800 ;
  LAYER ME2 ;
  RECT 619.780 449.680 623.320 450.800 ;
  LAYER ME1 ;
  RECT 619.780 449.680 623.320 450.800 ;
 END
 PORT
  LAYER ME4 ;
  RECT 576.380 449.680 579.920 450.800 ;
  LAYER ME3 ;
  RECT 576.380 449.680 579.920 450.800 ;
  LAYER ME2 ;
  RECT 576.380 449.680 579.920 450.800 ;
  LAYER ME1 ;
  RECT 576.380 449.680 579.920 450.800 ;
 END
 PORT
  LAYER ME4 ;
  RECT 567.700 449.680 571.240 450.800 ;
  LAYER ME3 ;
  RECT 567.700 449.680 571.240 450.800 ;
  LAYER ME2 ;
  RECT 567.700 449.680 571.240 450.800 ;
  LAYER ME1 ;
  RECT 567.700 449.680 571.240 450.800 ;
 END
 PORT
  LAYER ME4 ;
  RECT 559.020 449.680 562.560 450.800 ;
  LAYER ME3 ;
  RECT 559.020 449.680 562.560 450.800 ;
  LAYER ME2 ;
  RECT 559.020 449.680 562.560 450.800 ;
  LAYER ME1 ;
  RECT 559.020 449.680 562.560 450.800 ;
 END
 PORT
  LAYER ME4 ;
  RECT 550.340 449.680 553.880 450.800 ;
  LAYER ME3 ;
  RECT 550.340 449.680 553.880 450.800 ;
  LAYER ME2 ;
  RECT 550.340 449.680 553.880 450.800 ;
  LAYER ME1 ;
  RECT 550.340 449.680 553.880 450.800 ;
 END
 PORT
  LAYER ME4 ;
  RECT 541.660 449.680 545.200 450.800 ;
  LAYER ME3 ;
  RECT 541.660 449.680 545.200 450.800 ;
  LAYER ME2 ;
  RECT 541.660 449.680 545.200 450.800 ;
  LAYER ME1 ;
  RECT 541.660 449.680 545.200 450.800 ;
 END
 PORT
  LAYER ME4 ;
  RECT 532.980 449.680 536.520 450.800 ;
  LAYER ME3 ;
  RECT 532.980 449.680 536.520 450.800 ;
  LAYER ME2 ;
  RECT 532.980 449.680 536.520 450.800 ;
  LAYER ME1 ;
  RECT 532.980 449.680 536.520 450.800 ;
 END
 PORT
  LAYER ME4 ;
  RECT 489.580 449.680 493.120 450.800 ;
  LAYER ME3 ;
  RECT 489.580 449.680 493.120 450.800 ;
  LAYER ME2 ;
  RECT 489.580 449.680 493.120 450.800 ;
  LAYER ME1 ;
  RECT 489.580 449.680 493.120 450.800 ;
 END
 PORT
  LAYER ME4 ;
  RECT 480.900 449.680 484.440 450.800 ;
  LAYER ME3 ;
  RECT 480.900 449.680 484.440 450.800 ;
  LAYER ME2 ;
  RECT 480.900 449.680 484.440 450.800 ;
  LAYER ME1 ;
  RECT 480.900 449.680 484.440 450.800 ;
 END
 PORT
  LAYER ME4 ;
  RECT 472.220 449.680 475.760 450.800 ;
  LAYER ME3 ;
  RECT 472.220 449.680 475.760 450.800 ;
  LAYER ME2 ;
  RECT 472.220 449.680 475.760 450.800 ;
  LAYER ME1 ;
  RECT 472.220 449.680 475.760 450.800 ;
 END
 PORT
  LAYER ME4 ;
  RECT 463.540 449.680 467.080 450.800 ;
  LAYER ME3 ;
  RECT 463.540 449.680 467.080 450.800 ;
  LAYER ME2 ;
  RECT 463.540 449.680 467.080 450.800 ;
  LAYER ME1 ;
  RECT 463.540 449.680 467.080 450.800 ;
 END
 PORT
  LAYER ME4 ;
  RECT 454.860 449.680 458.400 450.800 ;
  LAYER ME3 ;
  RECT 454.860 449.680 458.400 450.800 ;
  LAYER ME2 ;
  RECT 454.860 449.680 458.400 450.800 ;
  LAYER ME1 ;
  RECT 454.860 449.680 458.400 450.800 ;
 END
 PORT
  LAYER ME4 ;
  RECT 446.180 449.680 449.720 450.800 ;
  LAYER ME3 ;
  RECT 446.180 449.680 449.720 450.800 ;
  LAYER ME2 ;
  RECT 446.180 449.680 449.720 450.800 ;
  LAYER ME1 ;
  RECT 446.180 449.680 449.720 450.800 ;
 END
 PORT
  LAYER ME4 ;
  RECT 402.780 449.680 406.320 450.800 ;
  LAYER ME3 ;
  RECT 402.780 449.680 406.320 450.800 ;
  LAYER ME2 ;
  RECT 402.780 449.680 406.320 450.800 ;
  LAYER ME1 ;
  RECT 402.780 449.680 406.320 450.800 ;
 END
 PORT
  LAYER ME4 ;
  RECT 394.100 449.680 397.640 450.800 ;
  LAYER ME3 ;
  RECT 394.100 449.680 397.640 450.800 ;
  LAYER ME2 ;
  RECT 394.100 449.680 397.640 450.800 ;
  LAYER ME1 ;
  RECT 394.100 449.680 397.640 450.800 ;
 END
 PORT
  LAYER ME4 ;
  RECT 385.420 449.680 388.960 450.800 ;
  LAYER ME3 ;
  RECT 385.420 449.680 388.960 450.800 ;
  LAYER ME2 ;
  RECT 385.420 449.680 388.960 450.800 ;
  LAYER ME1 ;
  RECT 385.420 449.680 388.960 450.800 ;
 END
 PORT
  LAYER ME4 ;
  RECT 376.740 449.680 380.280 450.800 ;
  LAYER ME3 ;
  RECT 376.740 449.680 380.280 450.800 ;
  LAYER ME2 ;
  RECT 376.740 449.680 380.280 450.800 ;
  LAYER ME1 ;
  RECT 376.740 449.680 380.280 450.800 ;
 END
 PORT
  LAYER ME4 ;
  RECT 368.060 449.680 371.600 450.800 ;
  LAYER ME3 ;
  RECT 368.060 449.680 371.600 450.800 ;
  LAYER ME2 ;
  RECT 368.060 449.680 371.600 450.800 ;
  LAYER ME1 ;
  RECT 368.060 449.680 371.600 450.800 ;
 END
 PORT
  LAYER ME4 ;
  RECT 359.380 449.680 362.920 450.800 ;
  LAYER ME3 ;
  RECT 359.380 449.680 362.920 450.800 ;
  LAYER ME2 ;
  RECT 359.380 449.680 362.920 450.800 ;
  LAYER ME1 ;
  RECT 359.380 449.680 362.920 450.800 ;
 END
 PORT
  LAYER ME4 ;
  RECT 315.980 449.680 319.520 450.800 ;
  LAYER ME3 ;
  RECT 315.980 449.680 319.520 450.800 ;
  LAYER ME2 ;
  RECT 315.980 449.680 319.520 450.800 ;
  LAYER ME1 ;
  RECT 315.980 449.680 319.520 450.800 ;
 END
 PORT
  LAYER ME4 ;
  RECT 307.300 449.680 310.840 450.800 ;
  LAYER ME3 ;
  RECT 307.300 449.680 310.840 450.800 ;
  LAYER ME2 ;
  RECT 307.300 449.680 310.840 450.800 ;
  LAYER ME1 ;
  RECT 307.300 449.680 310.840 450.800 ;
 END
 PORT
  LAYER ME4 ;
  RECT 298.620 449.680 302.160 450.800 ;
  LAYER ME3 ;
  RECT 298.620 449.680 302.160 450.800 ;
  LAYER ME2 ;
  RECT 298.620 449.680 302.160 450.800 ;
  LAYER ME1 ;
  RECT 298.620 449.680 302.160 450.800 ;
 END
 PORT
  LAYER ME4 ;
  RECT 289.940 449.680 293.480 450.800 ;
  LAYER ME3 ;
  RECT 289.940 449.680 293.480 450.800 ;
  LAYER ME2 ;
  RECT 289.940 449.680 293.480 450.800 ;
  LAYER ME1 ;
  RECT 289.940 449.680 293.480 450.800 ;
 END
 PORT
  LAYER ME4 ;
  RECT 281.260 449.680 284.800 450.800 ;
  LAYER ME3 ;
  RECT 281.260 449.680 284.800 450.800 ;
  LAYER ME2 ;
  RECT 281.260 449.680 284.800 450.800 ;
  LAYER ME1 ;
  RECT 281.260 449.680 284.800 450.800 ;
 END
 PORT
  LAYER ME4 ;
  RECT 272.580 449.680 276.120 450.800 ;
  LAYER ME3 ;
  RECT 272.580 449.680 276.120 450.800 ;
  LAYER ME2 ;
  RECT 272.580 449.680 276.120 450.800 ;
  LAYER ME1 ;
  RECT 272.580 449.680 276.120 450.800 ;
 END
 PORT
  LAYER ME4 ;
  RECT 229.180 449.680 232.720 450.800 ;
  LAYER ME3 ;
  RECT 229.180 449.680 232.720 450.800 ;
  LAYER ME2 ;
  RECT 229.180 449.680 232.720 450.800 ;
  LAYER ME1 ;
  RECT 229.180 449.680 232.720 450.800 ;
 END
 PORT
  LAYER ME4 ;
  RECT 220.500 449.680 224.040 450.800 ;
  LAYER ME3 ;
  RECT 220.500 449.680 224.040 450.800 ;
  LAYER ME2 ;
  RECT 220.500 449.680 224.040 450.800 ;
  LAYER ME1 ;
  RECT 220.500 449.680 224.040 450.800 ;
 END
 PORT
  LAYER ME4 ;
  RECT 211.820 449.680 215.360 450.800 ;
  LAYER ME3 ;
  RECT 211.820 449.680 215.360 450.800 ;
  LAYER ME2 ;
  RECT 211.820 449.680 215.360 450.800 ;
  LAYER ME1 ;
  RECT 211.820 449.680 215.360 450.800 ;
 END
 PORT
  LAYER ME4 ;
  RECT 203.140 449.680 206.680 450.800 ;
  LAYER ME3 ;
  RECT 203.140 449.680 206.680 450.800 ;
  LAYER ME2 ;
  RECT 203.140 449.680 206.680 450.800 ;
  LAYER ME1 ;
  RECT 203.140 449.680 206.680 450.800 ;
 END
 PORT
  LAYER ME4 ;
  RECT 194.460 449.680 198.000 450.800 ;
  LAYER ME3 ;
  RECT 194.460 449.680 198.000 450.800 ;
  LAYER ME2 ;
  RECT 194.460 449.680 198.000 450.800 ;
  LAYER ME1 ;
  RECT 194.460 449.680 198.000 450.800 ;
 END
 PORT
  LAYER ME4 ;
  RECT 185.780 449.680 189.320 450.800 ;
  LAYER ME3 ;
  RECT 185.780 449.680 189.320 450.800 ;
  LAYER ME2 ;
  RECT 185.780 449.680 189.320 450.800 ;
  LAYER ME1 ;
  RECT 185.780 449.680 189.320 450.800 ;
 END
 PORT
  LAYER ME4 ;
  RECT 142.380 449.680 145.920 450.800 ;
  LAYER ME3 ;
  RECT 142.380 449.680 145.920 450.800 ;
  LAYER ME2 ;
  RECT 142.380 449.680 145.920 450.800 ;
  LAYER ME1 ;
  RECT 142.380 449.680 145.920 450.800 ;
 END
 PORT
  LAYER ME4 ;
  RECT 133.700 449.680 137.240 450.800 ;
  LAYER ME3 ;
  RECT 133.700 449.680 137.240 450.800 ;
  LAYER ME2 ;
  RECT 133.700 449.680 137.240 450.800 ;
  LAYER ME1 ;
  RECT 133.700 449.680 137.240 450.800 ;
 END
 PORT
  LAYER ME4 ;
  RECT 125.020 449.680 128.560 450.800 ;
  LAYER ME3 ;
  RECT 125.020 449.680 128.560 450.800 ;
  LAYER ME2 ;
  RECT 125.020 449.680 128.560 450.800 ;
  LAYER ME1 ;
  RECT 125.020 449.680 128.560 450.800 ;
 END
 PORT
  LAYER ME4 ;
  RECT 116.340 449.680 119.880 450.800 ;
  LAYER ME3 ;
  RECT 116.340 449.680 119.880 450.800 ;
  LAYER ME2 ;
  RECT 116.340 449.680 119.880 450.800 ;
  LAYER ME1 ;
  RECT 116.340 449.680 119.880 450.800 ;
 END
 PORT
  LAYER ME4 ;
  RECT 107.660 449.680 111.200 450.800 ;
  LAYER ME3 ;
  RECT 107.660 449.680 111.200 450.800 ;
  LAYER ME2 ;
  RECT 107.660 449.680 111.200 450.800 ;
  LAYER ME1 ;
  RECT 107.660 449.680 111.200 450.800 ;
 END
 PORT
  LAYER ME4 ;
  RECT 98.980 449.680 102.520 450.800 ;
  LAYER ME3 ;
  RECT 98.980 449.680 102.520 450.800 ;
  LAYER ME2 ;
  RECT 98.980 449.680 102.520 450.800 ;
  LAYER ME1 ;
  RECT 98.980 449.680 102.520 450.800 ;
 END
 PORT
  LAYER ME4 ;
  RECT 55.580 449.680 59.120 450.800 ;
  LAYER ME3 ;
  RECT 55.580 449.680 59.120 450.800 ;
  LAYER ME2 ;
  RECT 55.580 449.680 59.120 450.800 ;
  LAYER ME1 ;
  RECT 55.580 449.680 59.120 450.800 ;
 END
 PORT
  LAYER ME4 ;
  RECT 46.900 449.680 50.440 450.800 ;
  LAYER ME3 ;
  RECT 46.900 449.680 50.440 450.800 ;
  LAYER ME2 ;
  RECT 46.900 449.680 50.440 450.800 ;
  LAYER ME1 ;
  RECT 46.900 449.680 50.440 450.800 ;
 END
 PORT
  LAYER ME4 ;
  RECT 38.220 449.680 41.760 450.800 ;
  LAYER ME3 ;
  RECT 38.220 449.680 41.760 450.800 ;
  LAYER ME2 ;
  RECT 38.220 449.680 41.760 450.800 ;
  LAYER ME1 ;
  RECT 38.220 449.680 41.760 450.800 ;
 END
 PORT
  LAYER ME4 ;
  RECT 29.540 449.680 33.080 450.800 ;
  LAYER ME3 ;
  RECT 29.540 449.680 33.080 450.800 ;
  LAYER ME2 ;
  RECT 29.540 449.680 33.080 450.800 ;
  LAYER ME1 ;
  RECT 29.540 449.680 33.080 450.800 ;
 END
 PORT
  LAYER ME4 ;
  RECT 20.860 449.680 24.400 450.800 ;
  LAYER ME3 ;
  RECT 20.860 449.680 24.400 450.800 ;
  LAYER ME2 ;
  RECT 20.860 449.680 24.400 450.800 ;
  LAYER ME1 ;
  RECT 20.860 449.680 24.400 450.800 ;
 END
 PORT
  LAYER ME4 ;
  RECT 12.180 449.680 15.720 450.800 ;
  LAYER ME3 ;
  RECT 12.180 449.680 15.720 450.800 ;
  LAYER ME2 ;
  RECT 12.180 449.680 15.720 450.800 ;
  LAYER ME1 ;
  RECT 12.180 449.680 15.720 450.800 ;
 END
 PORT
  LAYER ME4 ;
  RECT 733.240 0.000 736.780 1.120 ;
  LAYER ME3 ;
  RECT 733.240 0.000 736.780 1.120 ;
  LAYER ME2 ;
  RECT 733.240 0.000 736.780 1.120 ;
  LAYER ME1 ;
  RECT 733.240 0.000 736.780 1.120 ;
 END
 PORT
  LAYER ME4 ;
  RECT 724.560 0.000 728.100 1.120 ;
  LAYER ME3 ;
  RECT 724.560 0.000 728.100 1.120 ;
  LAYER ME2 ;
  RECT 724.560 0.000 728.100 1.120 ;
  LAYER ME1 ;
  RECT 724.560 0.000 728.100 1.120 ;
 END
 PORT
  LAYER ME4 ;
  RECT 715.880 0.000 719.420 1.120 ;
  LAYER ME3 ;
  RECT 715.880 0.000 719.420 1.120 ;
  LAYER ME2 ;
  RECT 715.880 0.000 719.420 1.120 ;
  LAYER ME1 ;
  RECT 715.880 0.000 719.420 1.120 ;
 END
 PORT
  LAYER ME4 ;
  RECT 707.200 0.000 710.740 1.120 ;
  LAYER ME3 ;
  RECT 707.200 0.000 710.740 1.120 ;
  LAYER ME2 ;
  RECT 707.200 0.000 710.740 1.120 ;
  LAYER ME1 ;
  RECT 707.200 0.000 710.740 1.120 ;
 END
 PORT
  LAYER ME4 ;
  RECT 698.520 0.000 702.060 1.120 ;
  LAYER ME3 ;
  RECT 698.520 0.000 702.060 1.120 ;
  LAYER ME2 ;
  RECT 698.520 0.000 702.060 1.120 ;
  LAYER ME1 ;
  RECT 698.520 0.000 702.060 1.120 ;
 END
 PORT
  LAYER ME4 ;
  RECT 689.840 0.000 693.380 1.120 ;
  LAYER ME3 ;
  RECT 689.840 0.000 693.380 1.120 ;
  LAYER ME2 ;
  RECT 689.840 0.000 693.380 1.120 ;
  LAYER ME1 ;
  RECT 689.840 0.000 693.380 1.120 ;
 END
 PORT
  LAYER ME4 ;
  RECT 629.080 0.000 632.620 1.120 ;
  LAYER ME3 ;
  RECT 629.080 0.000 632.620 1.120 ;
  LAYER ME2 ;
  RECT 629.080 0.000 632.620 1.120 ;
  LAYER ME1 ;
  RECT 629.080 0.000 632.620 1.120 ;
 END
 PORT
  LAYER ME4 ;
  RECT 620.400 0.000 623.940 1.120 ;
  LAYER ME3 ;
  RECT 620.400 0.000 623.940 1.120 ;
  LAYER ME2 ;
  RECT 620.400 0.000 623.940 1.120 ;
  LAYER ME1 ;
  RECT 620.400 0.000 623.940 1.120 ;
 END
 PORT
  LAYER ME4 ;
  RECT 611.720 0.000 615.260 1.120 ;
  LAYER ME3 ;
  RECT 611.720 0.000 615.260 1.120 ;
  LAYER ME2 ;
  RECT 611.720 0.000 615.260 1.120 ;
  LAYER ME1 ;
  RECT 611.720 0.000 615.260 1.120 ;
 END
 PORT
  LAYER ME4 ;
  RECT 603.040 0.000 606.580 1.120 ;
  LAYER ME3 ;
  RECT 603.040 0.000 606.580 1.120 ;
  LAYER ME2 ;
  RECT 603.040 0.000 606.580 1.120 ;
  LAYER ME1 ;
  RECT 603.040 0.000 606.580 1.120 ;
 END
 PORT
  LAYER ME4 ;
  RECT 594.360 0.000 597.900 1.120 ;
  LAYER ME3 ;
  RECT 594.360 0.000 597.900 1.120 ;
  LAYER ME2 ;
  RECT 594.360 0.000 597.900 1.120 ;
  LAYER ME1 ;
  RECT 594.360 0.000 597.900 1.120 ;
 END
 PORT
  LAYER ME4 ;
  RECT 585.680 0.000 589.220 1.120 ;
  LAYER ME3 ;
  RECT 585.680 0.000 589.220 1.120 ;
  LAYER ME2 ;
  RECT 585.680 0.000 589.220 1.120 ;
  LAYER ME1 ;
  RECT 585.680 0.000 589.220 1.120 ;
 END
 PORT
  LAYER ME4 ;
  RECT 524.300 0.000 527.840 1.120 ;
  LAYER ME3 ;
  RECT 524.300 0.000 527.840 1.120 ;
  LAYER ME2 ;
  RECT 524.300 0.000 527.840 1.120 ;
  LAYER ME1 ;
  RECT 524.300 0.000 527.840 1.120 ;
 END
 PORT
  LAYER ME4 ;
  RECT 515.620 0.000 519.160 1.120 ;
  LAYER ME3 ;
  RECT 515.620 0.000 519.160 1.120 ;
  LAYER ME2 ;
  RECT 515.620 0.000 519.160 1.120 ;
  LAYER ME1 ;
  RECT 515.620 0.000 519.160 1.120 ;
 END
 PORT
  LAYER ME4 ;
  RECT 506.940 0.000 510.480 1.120 ;
  LAYER ME3 ;
  RECT 506.940 0.000 510.480 1.120 ;
  LAYER ME2 ;
  RECT 506.940 0.000 510.480 1.120 ;
  LAYER ME1 ;
  RECT 506.940 0.000 510.480 1.120 ;
 END
 PORT
  LAYER ME4 ;
  RECT 498.260 0.000 501.800 1.120 ;
  LAYER ME3 ;
  RECT 498.260 0.000 501.800 1.120 ;
  LAYER ME2 ;
  RECT 498.260 0.000 501.800 1.120 ;
  LAYER ME1 ;
  RECT 498.260 0.000 501.800 1.120 ;
 END
 PORT
  LAYER ME4 ;
  RECT 489.580 0.000 493.120 1.120 ;
  LAYER ME3 ;
  RECT 489.580 0.000 493.120 1.120 ;
  LAYER ME2 ;
  RECT 489.580 0.000 493.120 1.120 ;
  LAYER ME1 ;
  RECT 489.580 0.000 493.120 1.120 ;
 END
 PORT
  LAYER ME4 ;
  RECT 480.900 0.000 484.440 1.120 ;
  LAYER ME3 ;
  RECT 480.900 0.000 484.440 1.120 ;
  LAYER ME2 ;
  RECT 480.900 0.000 484.440 1.120 ;
  LAYER ME1 ;
  RECT 480.900 0.000 484.440 1.120 ;
 END
 PORT
  LAYER ME4 ;
  RECT 402.160 0.000 405.700 1.120 ;
  LAYER ME3 ;
  RECT 402.160 0.000 405.700 1.120 ;
  LAYER ME2 ;
  RECT 402.160 0.000 405.700 1.120 ;
  LAYER ME1 ;
  RECT 402.160 0.000 405.700 1.120 ;
 END
 PORT
  LAYER ME4 ;
  RECT 380.460 0.000 384.000 1.120 ;
  LAYER ME3 ;
  RECT 380.460 0.000 384.000 1.120 ;
  LAYER ME2 ;
  RECT 380.460 0.000 384.000 1.120 ;
  LAYER ME1 ;
  RECT 380.460 0.000 384.000 1.120 ;
 END
 PORT
  LAYER ME4 ;
  RECT 359.380 0.000 362.920 1.120 ;
  LAYER ME3 ;
  RECT 359.380 0.000 362.920 1.120 ;
  LAYER ME2 ;
  RECT 359.380 0.000 362.920 1.120 ;
  LAYER ME1 ;
  RECT 359.380 0.000 362.920 1.120 ;
 END
 PORT
  LAYER ME4 ;
  RECT 343.880 0.000 347.420 1.120 ;
  LAYER ME3 ;
  RECT 343.880 0.000 347.420 1.120 ;
  LAYER ME2 ;
  RECT 343.880 0.000 347.420 1.120 ;
  LAYER ME1 ;
  RECT 343.880 0.000 347.420 1.120 ;
 END
 PORT
  LAYER ME4 ;
  RECT 335.200 0.000 338.740 1.120 ;
  LAYER ME3 ;
  RECT 335.200 0.000 338.740 1.120 ;
  LAYER ME2 ;
  RECT 335.200 0.000 338.740 1.120 ;
  LAYER ME1 ;
  RECT 335.200 0.000 338.740 1.120 ;
 END
 PORT
  LAYER ME4 ;
  RECT 326.520 0.000 330.060 1.120 ;
  LAYER ME3 ;
  RECT 326.520 0.000 330.060 1.120 ;
  LAYER ME2 ;
  RECT 326.520 0.000 330.060 1.120 ;
  LAYER ME1 ;
  RECT 326.520 0.000 330.060 1.120 ;
 END
 PORT
  LAYER ME4 ;
  RECT 283.120 0.000 286.660 1.120 ;
  LAYER ME3 ;
  RECT 283.120 0.000 286.660 1.120 ;
  LAYER ME2 ;
  RECT 283.120 0.000 286.660 1.120 ;
  LAYER ME1 ;
  RECT 283.120 0.000 286.660 1.120 ;
 END
 PORT
  LAYER ME4 ;
  RECT 274.440 0.000 277.980 1.120 ;
  LAYER ME3 ;
  RECT 274.440 0.000 277.980 1.120 ;
  LAYER ME2 ;
  RECT 274.440 0.000 277.980 1.120 ;
  LAYER ME1 ;
  RECT 274.440 0.000 277.980 1.120 ;
 END
 PORT
  LAYER ME4 ;
  RECT 265.760 0.000 269.300 1.120 ;
  LAYER ME3 ;
  RECT 265.760 0.000 269.300 1.120 ;
  LAYER ME2 ;
  RECT 265.760 0.000 269.300 1.120 ;
  LAYER ME1 ;
  RECT 265.760 0.000 269.300 1.120 ;
 END
 PORT
  LAYER ME4 ;
  RECT 253.360 0.000 256.900 1.120 ;
  LAYER ME3 ;
  RECT 253.360 0.000 256.900 1.120 ;
  LAYER ME2 ;
  RECT 253.360 0.000 256.900 1.120 ;
  LAYER ME1 ;
  RECT 253.360 0.000 256.900 1.120 ;
 END
 PORT
  LAYER ME4 ;
  RECT 231.040 0.000 234.580 1.120 ;
  LAYER ME3 ;
  RECT 231.040 0.000 234.580 1.120 ;
  LAYER ME2 ;
  RECT 231.040 0.000 234.580 1.120 ;
  LAYER ME1 ;
  RECT 231.040 0.000 234.580 1.120 ;
 END
 PORT
  LAYER ME4 ;
  RECT 222.360 0.000 225.900 1.120 ;
  LAYER ME3 ;
  RECT 222.360 0.000 225.900 1.120 ;
  LAYER ME2 ;
  RECT 222.360 0.000 225.900 1.120 ;
  LAYER ME1 ;
  RECT 222.360 0.000 225.900 1.120 ;
 END
 PORT
  LAYER ME4 ;
  RECT 178.960 0.000 182.500 1.120 ;
  LAYER ME3 ;
  RECT 178.960 0.000 182.500 1.120 ;
  LAYER ME2 ;
  RECT 178.960 0.000 182.500 1.120 ;
  LAYER ME1 ;
  RECT 178.960 0.000 182.500 1.120 ;
 END
 PORT
  LAYER ME4 ;
  RECT 170.280 0.000 173.820 1.120 ;
  LAYER ME3 ;
  RECT 170.280 0.000 173.820 1.120 ;
  LAYER ME2 ;
  RECT 170.280 0.000 173.820 1.120 ;
  LAYER ME1 ;
  RECT 170.280 0.000 173.820 1.120 ;
 END
 PORT
  LAYER ME4 ;
  RECT 161.600 0.000 165.140 1.120 ;
  LAYER ME3 ;
  RECT 161.600 0.000 165.140 1.120 ;
  LAYER ME2 ;
  RECT 161.600 0.000 165.140 1.120 ;
  LAYER ME1 ;
  RECT 161.600 0.000 165.140 1.120 ;
 END
 PORT
  LAYER ME4 ;
  RECT 152.920 0.000 156.460 1.120 ;
  LAYER ME3 ;
  RECT 152.920 0.000 156.460 1.120 ;
  LAYER ME2 ;
  RECT 152.920 0.000 156.460 1.120 ;
  LAYER ME1 ;
  RECT 152.920 0.000 156.460 1.120 ;
 END
 PORT
  LAYER ME4 ;
  RECT 139.900 0.000 143.440 1.120 ;
  LAYER ME3 ;
  RECT 139.900 0.000 143.440 1.120 ;
  LAYER ME2 ;
  RECT 139.900 0.000 143.440 1.120 ;
  LAYER ME1 ;
  RECT 139.900 0.000 143.440 1.120 ;
 END
 PORT
  LAYER ME4 ;
  RECT 118.200 0.000 121.740 1.120 ;
  LAYER ME3 ;
  RECT 118.200 0.000 121.740 1.120 ;
  LAYER ME2 ;
  RECT 118.200 0.000 121.740 1.120 ;
  LAYER ME1 ;
  RECT 118.200 0.000 121.740 1.120 ;
 END
 PORT
  LAYER ME4 ;
  RECT 74.800 0.000 78.340 1.120 ;
  LAYER ME3 ;
  RECT 74.800 0.000 78.340 1.120 ;
  LAYER ME2 ;
  RECT 74.800 0.000 78.340 1.120 ;
  LAYER ME1 ;
  RECT 74.800 0.000 78.340 1.120 ;
 END
 PORT
  LAYER ME4 ;
  RECT 66.120 0.000 69.660 1.120 ;
  LAYER ME3 ;
  RECT 66.120 0.000 69.660 1.120 ;
  LAYER ME2 ;
  RECT 66.120 0.000 69.660 1.120 ;
  LAYER ME1 ;
  RECT 66.120 0.000 69.660 1.120 ;
 END
 PORT
  LAYER ME4 ;
  RECT 57.440 0.000 60.980 1.120 ;
  LAYER ME3 ;
  RECT 57.440 0.000 60.980 1.120 ;
  LAYER ME2 ;
  RECT 57.440 0.000 60.980 1.120 ;
  LAYER ME1 ;
  RECT 57.440 0.000 60.980 1.120 ;
 END
 PORT
  LAYER ME4 ;
  RECT 48.760 0.000 52.300 1.120 ;
  LAYER ME3 ;
  RECT 48.760 0.000 52.300 1.120 ;
  LAYER ME2 ;
  RECT 48.760 0.000 52.300 1.120 ;
  LAYER ME1 ;
  RECT 48.760 0.000 52.300 1.120 ;
 END
 PORT
  LAYER ME4 ;
  RECT 40.080 0.000 43.620 1.120 ;
  LAYER ME3 ;
  RECT 40.080 0.000 43.620 1.120 ;
  LAYER ME2 ;
  RECT 40.080 0.000 43.620 1.120 ;
  LAYER ME1 ;
  RECT 40.080 0.000 43.620 1.120 ;
 END
 PORT
  LAYER ME4 ;
  RECT 27.060 0.000 30.600 1.120 ;
  LAYER ME3 ;
  RECT 27.060 0.000 30.600 1.120 ;
  LAYER ME2 ;
  RECT 27.060 0.000 30.600 1.120 ;
  LAYER ME1 ;
  RECT 27.060 0.000 30.600 1.120 ;
 END
END GND
PIN DO11
  DIRECTION OUTPUT ;
  CAPACITANCE 0.116 ;
 PORT
  LAYER ME4 ;
  RECT 678.960 0.000 680.080 1.120 ;
  LAYER ME3 ;
  RECT 678.960 0.000 680.080 1.120 ;
  LAYER ME2 ;
  RECT 678.960 0.000 680.080 1.120 ;
  LAYER ME1 ;
  RECT 678.960 0.000 680.080 1.120 ;
 END
END DO11
PIN DI11
  DIRECTION INPUT ;
  CAPACITANCE 0.039 ;
 PORT
  LAYER ME4 ;
  RECT 670.900 0.000 672.020 1.120 ;
  LAYER ME3 ;
  RECT 670.900 0.000 672.020 1.120 ;
  LAYER ME2 ;
  RECT 670.900 0.000 672.020 1.120 ;
  LAYER ME1 ;
  RECT 670.900 0.000 672.020 1.120 ;
 END
END DI11
PIN DO10
  DIRECTION OUTPUT ;
  CAPACITANCE 0.116 ;
 PORT
  LAYER ME4 ;
  RECT 665.940 0.000 667.060 1.120 ;
  LAYER ME3 ;
  RECT 665.940 0.000 667.060 1.120 ;
  LAYER ME2 ;
  RECT 665.940 0.000 667.060 1.120 ;
  LAYER ME1 ;
  RECT 665.940 0.000 667.060 1.120 ;
 END
END DO10
PIN DI10
  DIRECTION INPUT ;
  CAPACITANCE 0.039 ;
 PORT
  LAYER ME4 ;
  RECT 657.260 0.000 658.380 1.120 ;
  LAYER ME3 ;
  RECT 657.260 0.000 658.380 1.120 ;
  LAYER ME2 ;
  RECT 657.260 0.000 658.380 1.120 ;
  LAYER ME1 ;
  RECT 657.260 0.000 658.380 1.120 ;
 END
END DI10
PIN DO9
  DIRECTION OUTPUT ;
  CAPACITANCE 0.116 ;
 PORT
  LAYER ME4 ;
  RECT 566.120 0.000 567.240 1.120 ;
  LAYER ME3 ;
  RECT 566.120 0.000 567.240 1.120 ;
  LAYER ME2 ;
  RECT 566.120 0.000 567.240 1.120 ;
  LAYER ME1 ;
  RECT 566.120 0.000 567.240 1.120 ;
 END
END DO9
PIN DI9
  DIRECTION INPUT ;
  CAPACITANCE 0.039 ;
 PORT
  LAYER ME4 ;
  RECT 557.440 0.000 558.560 1.120 ;
  LAYER ME3 ;
  RECT 557.440 0.000 558.560 1.120 ;
  LAYER ME2 ;
  RECT 557.440 0.000 558.560 1.120 ;
  LAYER ME1 ;
  RECT 557.440 0.000 558.560 1.120 ;
 END
END DI9
PIN DO8
  DIRECTION OUTPUT ;
  CAPACITANCE 0.116 ;
 PORT
  LAYER ME4 ;
  RECT 552.480 0.000 553.600 1.120 ;
  LAYER ME3 ;
  RECT 552.480 0.000 553.600 1.120 ;
  LAYER ME2 ;
  RECT 552.480 0.000 553.600 1.120 ;
  LAYER ME1 ;
  RECT 552.480 0.000 553.600 1.120 ;
 END
END DO8
PIN DI8
  DIRECTION INPUT ;
  CAPACITANCE 0.039 ;
 PORT
  LAYER ME4 ;
  RECT 544.420 0.000 545.540 1.120 ;
  LAYER ME3 ;
  RECT 544.420 0.000 545.540 1.120 ;
  LAYER ME2 ;
  RECT 544.420 0.000 545.540 1.120 ;
  LAYER ME1 ;
  RECT 544.420 0.000 545.540 1.120 ;
 END
END DI8
PIN DO7
  DIRECTION OUTPUT ;
  CAPACITANCE 0.116 ;
 PORT
  LAYER ME4 ;
  RECT 452.660 0.000 453.780 1.120 ;
  LAYER ME3 ;
  RECT 452.660 0.000 453.780 1.120 ;
  LAYER ME2 ;
  RECT 452.660 0.000 453.780 1.120 ;
  LAYER ME1 ;
  RECT 452.660 0.000 453.780 1.120 ;
 END
END DO7
PIN DI7
  DIRECTION INPUT ;
  CAPACITANCE 0.039 ;
 PORT
  LAYER ME4 ;
  RECT 444.600 0.000 445.720 1.120 ;
  LAYER ME3 ;
  RECT 444.600 0.000 445.720 1.120 ;
  LAYER ME2 ;
  RECT 444.600 0.000 445.720 1.120 ;
  LAYER ME1 ;
  RECT 444.600 0.000 445.720 1.120 ;
 END
END DI7
PIN DO6
  DIRECTION OUTPUT ;
  CAPACITANCE 0.116 ;
 PORT
  LAYER ME4 ;
  RECT 439.640 0.000 440.760 1.120 ;
  LAYER ME3 ;
  RECT 439.640 0.000 440.760 1.120 ;
  LAYER ME2 ;
  RECT 439.640 0.000 440.760 1.120 ;
  LAYER ME1 ;
  RECT 439.640 0.000 440.760 1.120 ;
 END
END DO6
PIN DI6
  DIRECTION INPUT ;
  CAPACITANCE 0.039 ;
 PORT
  LAYER ME4 ;
  RECT 430.960 0.000 432.080 1.120 ;
  LAYER ME3 ;
  RECT 430.960 0.000 432.080 1.120 ;
  LAYER ME2 ;
  RECT 430.960 0.000 432.080 1.120 ;
  LAYER ME1 ;
  RECT 430.960 0.000 432.080 1.120 ;
 END
END DI6
PIN A1
  DIRECTION INPUT ;
  CAPACITANCE 0.027 ;
 PORT
  LAYER ME4 ;
  RECT 425.380 0.000 426.500 1.120 ;
  LAYER ME3 ;
  RECT 425.380 0.000 426.500 1.120 ;
  LAYER ME2 ;
  RECT 425.380 0.000 426.500 1.120 ;
  LAYER ME1 ;
  RECT 425.380 0.000 426.500 1.120 ;
 END
END A1
PIN WEB
  DIRECTION INPUT ;
  CAPACITANCE 0.011 ;
 PORT
  LAYER ME4 ;
  RECT 423.520 0.000 424.640 1.120 ;
  LAYER ME3 ;
  RECT 423.520 0.000 424.640 1.120 ;
  LAYER ME2 ;
  RECT 423.520 0.000 424.640 1.120 ;
  LAYER ME1 ;
  RECT 423.520 0.000 424.640 1.120 ;
 END
END WEB
PIN OE
  DIRECTION INPUT ;
  CAPACITANCE 0.033 ;
 PORT
  LAYER ME4 ;
  RECT 419.180 0.000 420.300 1.120 ;
  LAYER ME3 ;
  RECT 419.180 0.000 420.300 1.120 ;
  LAYER ME2 ;
  RECT 419.180 0.000 420.300 1.120 ;
  LAYER ME1 ;
  RECT 419.180 0.000 420.300 1.120 ;
 END
END OE
PIN CS
  DIRECTION INPUT ;
  CAPACITANCE 0.123 ;
 PORT
  LAYER ME4 ;
  RECT 417.320 0.000 418.440 1.120 ;
  LAYER ME3 ;
  RECT 417.320 0.000 418.440 1.120 ;
  LAYER ME2 ;
  RECT 417.320 0.000 418.440 1.120 ;
  LAYER ME1 ;
  RECT 417.320 0.000 418.440 1.120 ;
 END
END CS
PIN A3
  DIRECTION INPUT ;
  CAPACITANCE 0.027 ;
 PORT
  LAYER ME4 ;
  RECT 415.460 0.000 416.580 1.120 ;
  LAYER ME3 ;
  RECT 415.460 0.000 416.580 1.120 ;
  LAYER ME2 ;
  RECT 415.460 0.000 416.580 1.120 ;
  LAYER ME1 ;
  RECT 415.460 0.000 416.580 1.120 ;
 END
END A3
PIN A4
  DIRECTION INPUT ;
  CAPACITANCE 0.027 ;
 PORT
  LAYER ME4 ;
  RECT 408.640 0.000 409.760 1.120 ;
  LAYER ME3 ;
  RECT 408.640 0.000 409.760 1.120 ;
  LAYER ME2 ;
  RECT 408.640 0.000 409.760 1.120 ;
  LAYER ME1 ;
  RECT 408.640 0.000 409.760 1.120 ;
 END
END A4
PIN A2
  DIRECTION INPUT ;
  CAPACITANCE 0.027 ;
 PORT
  LAYER ME4 ;
  RECT 395.620 0.000 396.740 1.120 ;
  LAYER ME3 ;
  RECT 395.620 0.000 396.740 1.120 ;
  LAYER ME2 ;
  RECT 395.620 0.000 396.740 1.120 ;
  LAYER ME1 ;
  RECT 395.620 0.000 396.740 1.120 ;
 END
END A2
PIN CK
  DIRECTION INPUT ;
  CAPACITANCE 0.063 ;
 PORT
  LAYER ME4 ;
  RECT 392.520 0.000 393.640 1.120 ;
  LAYER ME3 ;
  RECT 392.520 0.000 393.640 1.120 ;
  LAYER ME2 ;
  RECT 392.520 0.000 393.640 1.120 ;
  LAYER ME1 ;
  RECT 392.520 0.000 393.640 1.120 ;
 END
END CK
PIN A0
  DIRECTION INPUT ;
  CAPACITANCE 0.027 ;
 PORT
  LAYER ME4 ;
  RECT 390.040 0.000 391.160 1.120 ;
  LAYER ME3 ;
  RECT 390.040 0.000 391.160 1.120 ;
  LAYER ME2 ;
  RECT 390.040 0.000 391.160 1.120 ;
  LAYER ME1 ;
  RECT 390.040 0.000 391.160 1.120 ;
 END
END A0
PIN A5
  DIRECTION INPUT ;
  CAPACITANCE 0.027 ;
 PORT
  LAYER ME4 ;
  RECT 385.700 0.000 386.820 1.120 ;
  LAYER ME3 ;
  RECT 385.700 0.000 386.820 1.120 ;
  LAYER ME2 ;
  RECT 385.700 0.000 386.820 1.120 ;
  LAYER ME1 ;
  RECT 385.700 0.000 386.820 1.120 ;
 END
END A5
PIN A6
  DIRECTION INPUT ;
  CAPACITANCE 0.027 ;
 PORT
  LAYER ME4 ;
  RECT 378.260 0.000 379.380 1.120 ;
  LAYER ME3 ;
  RECT 378.260 0.000 379.380 1.120 ;
  LAYER ME2 ;
  RECT 378.260 0.000 379.380 1.120 ;
  LAYER ME1 ;
  RECT 378.260 0.000 379.380 1.120 ;
 END
END A6
PIN A7
  DIRECTION INPUT ;
  CAPACITANCE 0.027 ;
 PORT
  LAYER ME4 ;
  RECT 375.160 0.000 376.280 1.120 ;
  LAYER ME3 ;
  RECT 375.160 0.000 376.280 1.120 ;
  LAYER ME2 ;
  RECT 375.160 0.000 376.280 1.120 ;
  LAYER ME1 ;
  RECT 375.160 0.000 376.280 1.120 ;
 END
END A7
PIN A8
  DIRECTION INPUT ;
  CAPACITANCE 0.027 ;
 PORT
  LAYER ME4 ;
  RECT 367.720 0.000 368.840 1.120 ;
  LAYER ME3 ;
  RECT 367.720 0.000 368.840 1.120 ;
  LAYER ME2 ;
  RECT 367.720 0.000 368.840 1.120 ;
  LAYER ME1 ;
  RECT 367.720 0.000 368.840 1.120 ;
 END
END A8
PIN A9
  DIRECTION INPUT ;
  CAPACITANCE 0.027 ;
 PORT
  LAYER ME4 ;
  RECT 364.620 0.000 365.740 1.120 ;
  LAYER ME3 ;
  RECT 364.620 0.000 365.740 1.120 ;
  LAYER ME2 ;
  RECT 364.620 0.000 365.740 1.120 ;
  LAYER ME1 ;
  RECT 364.620 0.000 365.740 1.120 ;
 END
END A9
PIN A10
  DIRECTION INPUT ;
  CAPACITANCE 0.027 ;
 PORT
  LAYER ME4 ;
  RECT 357.180 0.000 358.300 1.120 ;
  LAYER ME3 ;
  RECT 357.180 0.000 358.300 1.120 ;
  LAYER ME2 ;
  RECT 357.180 0.000 358.300 1.120 ;
  LAYER ME1 ;
  RECT 357.180 0.000 358.300 1.120 ;
 END
END A10
PIN A11
  DIRECTION INPUT ;
  CAPACITANCE 0.027 ;
 PORT
  LAYER ME4 ;
  RECT 354.080 0.000 355.200 1.120 ;
  LAYER ME3 ;
  RECT 354.080 0.000 355.200 1.120 ;
  LAYER ME2 ;
  RECT 354.080 0.000 355.200 1.120 ;
  LAYER ME1 ;
  RECT 354.080 0.000 355.200 1.120 ;
 END
END A11
PIN DO5
  DIRECTION OUTPUT ;
  CAPACITANCE 0.116 ;
 PORT
  LAYER ME4 ;
  RECT 259.220 0.000 260.340 1.120 ;
  LAYER ME3 ;
  RECT 259.220 0.000 260.340 1.120 ;
  LAYER ME2 ;
  RECT 259.220 0.000 260.340 1.120 ;
  LAYER ME1 ;
  RECT 259.220 0.000 260.340 1.120 ;
 END
END DO5
PIN DI5
  DIRECTION INPUT ;
  CAPACITANCE 0.039 ;
 PORT
  LAYER ME4 ;
  RECT 251.160 0.000 252.280 1.120 ;
  LAYER ME3 ;
  RECT 251.160 0.000 252.280 1.120 ;
  LAYER ME2 ;
  RECT 251.160 0.000 252.280 1.120 ;
  LAYER ME1 ;
  RECT 251.160 0.000 252.280 1.120 ;
 END
END DI5
PIN DO4
  DIRECTION OUTPUT ;
  CAPACITANCE 0.116 ;
 PORT
  LAYER ME4 ;
  RECT 246.200 0.000 247.320 1.120 ;
  LAYER ME3 ;
  RECT 246.200 0.000 247.320 1.120 ;
  LAYER ME2 ;
  RECT 246.200 0.000 247.320 1.120 ;
  LAYER ME1 ;
  RECT 246.200 0.000 247.320 1.120 ;
 END
END DO4
PIN DI4
  DIRECTION INPUT ;
  CAPACITANCE 0.039 ;
 PORT
  LAYER ME4 ;
  RECT 237.520 0.000 238.640 1.120 ;
  LAYER ME3 ;
  RECT 237.520 0.000 238.640 1.120 ;
  LAYER ME2 ;
  RECT 237.520 0.000 238.640 1.120 ;
  LAYER ME1 ;
  RECT 237.520 0.000 238.640 1.120 ;
 END
END DI4
PIN DO3
  DIRECTION OUTPUT ;
  CAPACITANCE 0.116 ;
 PORT
  LAYER ME4 ;
  RECT 146.380 0.000 147.500 1.120 ;
  LAYER ME3 ;
  RECT 146.380 0.000 147.500 1.120 ;
  LAYER ME2 ;
  RECT 146.380 0.000 147.500 1.120 ;
  LAYER ME1 ;
  RECT 146.380 0.000 147.500 1.120 ;
 END
END DO3
PIN DI3
  DIRECTION INPUT ;
  CAPACITANCE 0.039 ;
 PORT
  LAYER ME4 ;
  RECT 137.700 0.000 138.820 1.120 ;
  LAYER ME3 ;
  RECT 137.700 0.000 138.820 1.120 ;
  LAYER ME2 ;
  RECT 137.700 0.000 138.820 1.120 ;
  LAYER ME1 ;
  RECT 137.700 0.000 138.820 1.120 ;
 END
END DI3
PIN DO2
  DIRECTION OUTPUT ;
  CAPACITANCE 0.116 ;
 PORT
  LAYER ME4 ;
  RECT 133.360 0.000 134.480 1.120 ;
  LAYER ME3 ;
  RECT 133.360 0.000 134.480 1.120 ;
  LAYER ME2 ;
  RECT 133.360 0.000 134.480 1.120 ;
  LAYER ME1 ;
  RECT 133.360 0.000 134.480 1.120 ;
 END
END DO2
PIN DI2
  DIRECTION INPUT ;
  CAPACITANCE 0.039 ;
 PORT
  LAYER ME4 ;
  RECT 124.680 0.000 125.800 1.120 ;
  LAYER ME3 ;
  RECT 124.680 0.000 125.800 1.120 ;
  LAYER ME2 ;
  RECT 124.680 0.000 125.800 1.120 ;
  LAYER ME1 ;
  RECT 124.680 0.000 125.800 1.120 ;
 END
END DI2
PIN DO1
  DIRECTION OUTPUT ;
  CAPACITANCE 0.116 ;
 PORT
  LAYER ME4 ;
  RECT 33.540 0.000 34.660 1.120 ;
  LAYER ME3 ;
  RECT 33.540 0.000 34.660 1.120 ;
  LAYER ME2 ;
  RECT 33.540 0.000 34.660 1.120 ;
  LAYER ME1 ;
  RECT 33.540 0.000 34.660 1.120 ;
 END
END DO1
PIN DI1
  DIRECTION INPUT ;
  CAPACITANCE 0.039 ;
 PORT
  LAYER ME4 ;
  RECT 24.860 0.000 25.980 1.120 ;
  LAYER ME3 ;
  RECT 24.860 0.000 25.980 1.120 ;
  LAYER ME2 ;
  RECT 24.860 0.000 25.980 1.120 ;
  LAYER ME1 ;
  RECT 24.860 0.000 25.980 1.120 ;
 END
END DI1
PIN DO0
  DIRECTION OUTPUT ;
  CAPACITANCE 0.116 ;
 PORT
  LAYER ME4 ;
  RECT 19.900 0.000 21.020 1.120 ;
  LAYER ME3 ;
  RECT 19.900 0.000 21.020 1.120 ;
  LAYER ME2 ;
  RECT 19.900 0.000 21.020 1.120 ;
  LAYER ME1 ;
  RECT 19.900 0.000 21.020 1.120 ;
 END
END DO0
PIN DI0
  DIRECTION INPUT ;
  CAPACITANCE 0.039 ;
 PORT
  LAYER ME4 ;
  RECT 11.840 0.000 12.960 1.120 ;
  LAYER ME3 ;
  RECT 11.840 0.000 12.960 1.120 ;
  LAYER ME2 ;
  RECT 11.840 0.000 12.960 1.120 ;
  LAYER ME1 ;
  RECT 11.840 0.000 12.960 1.120 ;
 END
END DI0
OBS
  LAYER ME1 SPACING 0.280 ;
  RECT 0.000 0.140 778.720 450.800 ;
  LAYER ME2 SPACING 0.320 ;
  RECT 0.000 0.140 778.720 450.800 ;
  LAYER ME3 SPACING 0.320 ;
  RECT 0.000 0.140 778.720 450.800 ;
  LAYER ME4 SPACING 0.600 ;
  RECT 0.000 0.140 778.720 450.800 ;
  LAYER VI1 ;
  RECT 0.000 0.140 778.720 450.800 ;
  LAYER VI2 ;
  RECT 0.000 0.140 778.720 450.800 ;
  LAYER VI3 ;
  RECT 0.000 0.140 778.720 450.800 ;
END
END SUMA180_4096X12
END LIBRARY



